VERSION 5.7 ;
  NOWIREEXTENSIONATPIN ON ;
  DIVIDERCHAR "/" ;
  BUSBITCHARS "[]" ;
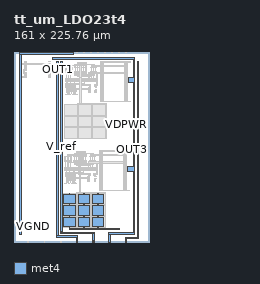
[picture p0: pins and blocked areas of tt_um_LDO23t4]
MACRO tt_um_LDO23t4
  CLASS BLOCK ;
  FOREIGN tt_um_LDO23t4 ;
  ORIGIN 0.000 0.000 ;
  SIZE 161.000 BY 225.760 ;
  PIN OUT3
    DIRECTION OUTPUT ;
    ANTENNAGATEAREA 46.000000 ;
    ANTENNADIFFAREA 186.759995 ;
    PORT
      LAYER met4 ;
        RECT 65.655 56.800 66.175 57.795 ;
        RECT 82.715 56.800 83.235 57.795 ;
        RECT 99.775 56.800 100.295 57.795 ;
        RECT 59.110 45.190 72.720 56.800 ;
        RECT 76.170 45.190 89.780 56.800 ;
        RECT 93.230 45.190 106.840 56.800 ;
        RECT 65.655 43.200 66.175 45.190 ;
        RECT 82.715 43.200 83.235 45.190 ;
        RECT 99.775 43.200 100.295 45.190 ;
        RECT 59.110 31.590 72.720 43.200 ;
        RECT 76.170 31.590 89.780 43.200 ;
        RECT 93.230 31.590 106.840 43.200 ;
        RECT 65.655 29.600 66.175 31.590 ;
        RECT 82.715 29.600 83.235 31.590 ;
        RECT 99.775 29.600 100.295 31.590 ;
        RECT 59.110 17.990 72.720 29.600 ;
        RECT 76.170 17.990 89.780 29.600 ;
        RECT 93.230 17.990 106.840 29.600 ;
        RECT 65.655 16.615 66.360 17.990 ;
        RECT 82.630 16.615 83.335 17.990 ;
        RECT 99.530 16.615 100.565 17.990 ;
        RECT 65.595 14.805 125.650 16.615 ;
        RECT 146.495 5.725 148.495 214.950 ;
        RECT 132.100 3.725 148.495 5.725 ;
        RECT 132.105 2.385 134.105 3.725 ;
        RECT 132.100 1.800 134.105 2.385 ;
        RECT 132.105 1.620 134.105 1.800 ;
        RECT 132.110 1.000 134.105 1.620 ;
        RECT 132.110 0.005 134.110 1.000 ;
        RECT 132.490 0.000 133.390 0.005 ;
    END
  END OUT2
  PIN V_ref
    DIRECTION INPUT ;
    USE POWER ;
    PORT
      LAYER met4 ;
        RECT 55.775 12.630 57.775 214.950 ;
        RECT 55.775 11.815 57.780 12.630 ;
        RECT 55.775 11.810 91.580 11.815 ;
        RECT 55.775 9.815 95.175 11.810 ;
        RECT 93.175 1.570 95.175 9.815 ;
        RECT 93.180 1.000 95.175 1.570 ;
        RECT 93.180 0.000 95.180 1.000 ;
    END
  END V_ref
  PIN VGND
    DIRECTION INOUT ;
    USE GROUND ;
    PORT
      LAYER met4 ;
        RECT 30.670 224.760 30.970 225.760 ;
        RECT 33.430 224.760 33.730 225.760 ;
        RECT 36.190 224.760 36.490 225.760 ;
        RECT 38.950 224.760 39.250 225.760 ;
        RECT 41.710 224.760 42.010 225.760 ;
        RECT 44.470 224.760 44.770 225.760 ;
        RECT 47.230 224.760 47.530 225.760 ;
        RECT 49.990 224.760 50.290 225.760 ;
        RECT 52.750 224.760 53.050 225.760 ;
        RECT 55.510 224.760 55.810 225.760 ;
        RECT 58.270 224.760 58.570 225.760 ;
        RECT 61.030 224.760 61.330 225.760 ;
        RECT 63.790 224.760 64.090 225.760 ;
        RECT 66.550 224.760 66.850 225.760 ;
        RECT 68.720 224.760 70.355 225.760 ;
        RECT 6.770 222.835 70.355 224.760 ;
        RECT 6.770 8.490 8.770 222.835 ;
    END
  END VGND
  PIN VDPWR
    DIRECTION INOUT ;
    USE POWER ;
    PORT
      LAYER met4 ;
        RECT 46.205 217.160 143.725 219.085 ;
        RECT 141.725 194.975 143.725 217.160 ;
        RECT 135.650 189.520 143.725 194.975 ;
        RECT 141.725 89.175 143.725 189.520 ;
        RECT 134.815 83.720 143.725 89.175 ;
        RECT 141.725 10.910 143.725 83.720 ;
        RECT 112.690 8.910 143.725 10.910 ;
        RECT 112.690 0.000 114.690 8.910 ;
    END
  END VDPWR
  PIN OUT1
    DIRECTION OUTPUT ;
    USE SIGNAL ;
    PORT
      LAYER met4 ;
        RECT 50.995 7.790 53.005 214.950 ;
        RECT 70.380 7.795 75.985 7.800 ;
        RECT 54.605 7.790 75.985 7.795 ;
        RECT 50.995 5.790 75.985 7.790 ;
        RECT 73.965 0.000 75.985 5.790 ;
    END
  END OUT1
  OBS
      LAYER pwell ;
        RECT 60.880 193.420 69.170 194.180 ;
        RECT 69.750 193.420 85.780 194.180 ;
        RECT 86.350 193.420 97.220 194.180 ;
        RECT 60.880 191.830 69.170 192.590 ;
        RECT 69.750 191.830 85.780 192.590 ;
        RECT 86.350 191.830 97.220 192.590 ;
        RECT 60.880 190.240 69.170 191.000 ;
        RECT 69.750 190.240 85.780 191.000 ;
        RECT 86.350 190.240 97.220 191.000 ;
        RECT 60.040 87.625 68.330 88.385 ;
        RECT 68.910 87.625 84.940 88.385 ;
        RECT 85.510 87.625 96.380 88.385 ;
        RECT 60.040 86.035 68.330 86.795 ;
        RECT 68.910 86.035 84.940 86.795 ;
        RECT 85.510 86.035 96.380 86.795 ;
        RECT 60.040 84.445 68.330 85.205 ;
        RECT 68.910 84.445 84.940 85.205 ;
        RECT 85.510 84.445 96.380 85.205 ;
      LAYER li1 ;
        RECT 12.540 214.520 14.700 214.870 ;
        RECT 40.790 214.520 42.950 214.870 ;
        RECT 12.540 213.690 14.700 214.040 ;
        RECT 102.550 213.740 103.550 213.910 ;
        RECT 103.840 213.740 104.840 213.910 ;
        RECT 105.130 213.740 106.130 213.910 ;
        RECT 106.420 213.740 107.420 213.910 ;
        RECT 107.710 213.740 108.710 213.910 ;
        RECT 109.000 213.740 110.000 213.910 ;
        RECT 110.290 213.740 111.290 213.910 ;
        RECT 111.580 213.740 112.580 213.910 ;
        RECT 112.870 213.740 113.870 213.910 ;
        RECT 114.160 213.740 115.160 213.910 ;
        RECT 115.450 213.740 116.450 213.910 ;
        RECT 116.740 213.740 117.740 213.910 ;
        RECT 121.750 213.740 122.750 213.910 ;
        RECT 123.040 213.740 124.040 213.910 ;
        RECT 124.330 213.740 125.330 213.910 ;
        RECT 125.620 213.740 126.620 213.910 ;
        RECT 126.910 213.740 127.910 213.910 ;
        RECT 128.200 213.740 129.200 213.910 ;
        RECT 129.490 213.740 130.490 213.910 ;
        RECT 130.780 213.740 131.780 213.910 ;
        RECT 132.070 213.740 133.070 213.910 ;
        RECT 133.360 213.740 134.360 213.910 ;
        RECT 134.650 213.740 135.650 213.910 ;
        RECT 135.940 213.740 136.940 213.910 ;
        RECT 137.230 213.740 138.230 213.910 ;
        RECT 12.540 212.860 14.700 213.210 ;
        RECT 12.540 212.030 14.700 212.380 ;
        RECT 40.790 212.030 42.950 212.380 ;
        RECT 12.540 209.830 14.700 210.180 ;
        RECT 40.790 209.830 42.950 210.180 ;
        RECT 12.540 209.000 14.700 209.350 ;
        RECT 12.540 208.170 14.700 208.520 ;
        RECT 40.790 208.170 42.950 208.520 ;
        RECT 12.540 207.340 14.700 207.690 ;
        RECT 40.790 207.340 42.950 207.690 ;
        RECT 61.300 207.560 62.300 207.730 ;
        RECT 62.695 207.560 63.485 207.730 ;
        RECT 63.985 207.560 64.775 207.730 ;
        RECT 65.275 207.560 66.065 207.730 ;
        RECT 66.565 207.560 67.355 207.730 ;
        RECT 67.750 207.560 68.750 207.730 ;
        RECT 71.575 207.560 72.365 207.730 ;
        RECT 72.865 207.560 73.655 207.730 ;
        RECT 74.155 207.560 74.945 207.730 ;
        RECT 75.445 207.560 76.235 207.730 ;
        RECT 76.735 207.560 77.525 207.730 ;
        RECT 78.025 207.560 78.815 207.730 ;
        RECT 79.315 207.560 80.105 207.730 ;
        RECT 80.605 207.560 81.395 207.730 ;
        RECT 81.895 207.560 82.685 207.730 ;
        RECT 83.185 207.560 83.975 207.730 ;
        RECT 84.475 207.560 85.265 207.730 ;
        RECT 85.765 207.560 86.555 207.730 ;
        RECT 90.755 207.560 91.545 207.730 ;
        RECT 92.045 207.560 92.835 207.730 ;
        RECT 93.335 207.560 94.125 207.730 ;
        RECT 94.625 207.560 95.415 207.730 ;
        RECT 95.915 207.560 96.705 207.730 ;
        RECT 97.205 207.560 97.995 207.730 ;
        RECT 12.540 206.510 14.700 206.860 ;
        RECT 40.790 206.510 42.950 206.860 ;
        RECT 12.540 205.680 14.700 206.030 ;
        RECT 40.790 205.680 42.950 206.030 ;
        RECT 12.540 204.850 14.700 205.200 ;
        RECT 40.790 204.850 42.950 205.200 ;
        RECT 12.540 204.020 14.700 204.370 ;
        RECT 40.790 204.020 42.950 204.370 ;
        RECT 12.540 203.190 14.700 203.540 ;
        RECT 40.790 203.190 42.950 203.540 ;
        RECT 61.070 202.305 61.240 207.345 ;
        RECT 62.360 202.305 62.530 207.345 ;
        RECT 64.940 202.305 65.110 207.345 ;
        RECT 67.520 202.305 67.690 207.345 ;
        RECT 68.810 202.305 68.980 207.345 ;
        RECT 72.530 202.305 72.700 207.345 ;
        RECT 75.110 202.305 75.280 207.345 ;
        RECT 77.690 202.305 77.860 207.345 ;
        RECT 80.270 202.305 80.440 207.345 ;
        RECT 82.850 202.305 83.020 207.345 ;
        RECT 85.430 202.305 85.600 207.345 ;
        RECT 91.710 202.305 91.880 207.345 ;
        RECT 94.290 202.305 94.460 207.345 ;
        RECT 96.870 202.305 97.040 207.345 ;
        RECT 61.300 201.920 62.300 202.090 ;
        RECT 62.695 201.920 63.485 202.090 ;
        RECT 63.985 201.920 64.775 202.090 ;
        RECT 65.275 201.920 66.065 202.090 ;
        RECT 66.565 201.920 67.355 202.090 ;
        RECT 67.750 201.920 68.750 202.090 ;
        RECT 71.575 201.920 72.365 202.090 ;
        RECT 72.865 201.920 73.655 202.090 ;
        RECT 74.155 201.920 74.945 202.090 ;
        RECT 75.445 201.920 76.235 202.090 ;
        RECT 76.735 201.920 77.525 202.090 ;
        RECT 78.025 201.920 78.815 202.090 ;
        RECT 79.315 201.920 80.105 202.090 ;
        RECT 80.605 201.920 81.395 202.090 ;
        RECT 81.895 201.920 82.685 202.090 ;
        RECT 83.185 201.920 83.975 202.090 ;
        RECT 84.475 201.920 85.265 202.090 ;
        RECT 85.765 201.920 86.555 202.090 ;
        RECT 90.755 201.920 91.545 202.090 ;
        RECT 92.045 201.920 92.835 202.090 ;
        RECT 93.335 201.920 94.125 202.090 ;
        RECT 94.625 201.920 95.415 202.090 ;
        RECT 95.915 201.920 96.705 202.090 ;
        RECT 97.205 201.920 97.995 202.090 ;
        RECT 12.540 200.990 14.700 201.340 ;
        RECT 40.790 200.990 42.950 201.340 ;
        RECT 12.540 200.160 14.700 200.510 ;
        RECT 40.790 200.160 42.950 200.510 ;
        RECT 12.540 199.330 14.700 199.680 ;
        RECT 40.790 199.330 42.950 199.680 ;
        RECT 12.540 198.500 14.700 198.850 ;
        RECT 40.790 198.500 42.950 198.850 ;
        RECT 12.540 197.670 14.700 198.020 ;
        RECT 40.790 197.670 42.950 198.020 ;
        RECT 12.540 196.840 14.700 197.190 ;
        RECT 40.790 196.840 42.950 197.190 ;
        RECT 12.540 196.010 14.700 196.360 ;
        RECT 40.790 196.010 42.950 196.360 ;
        RECT 12.540 195.180 14.700 195.530 ;
        RECT 40.790 195.180 42.950 195.530 ;
        RECT 61.405 192.650 62.195 192.820 ;
        RECT 62.695 192.650 63.485 192.820 ;
        RECT 66.565 192.650 67.355 192.820 ;
        RECT 67.855 192.650 68.645 192.820 ;
        RECT 71.565 192.650 72.355 192.820 ;
        RECT 72.855 192.650 73.645 192.820 ;
        RECT 74.145 192.650 74.935 192.820 ;
        RECT 75.435 192.650 76.225 192.820 ;
        RECT 76.725 192.650 77.515 192.820 ;
        RECT 78.015 192.650 78.805 192.820 ;
        RECT 79.305 192.650 80.095 192.820 ;
        RECT 80.595 192.650 81.385 192.820 ;
        RECT 81.885 192.650 82.675 192.820 ;
        RECT 83.175 192.650 83.965 192.820 ;
        RECT 88.165 192.650 88.955 192.820 ;
        RECT 89.455 192.650 90.245 192.820 ;
        RECT 90.745 192.650 91.535 192.820 ;
        RECT 92.035 192.650 92.825 192.820 ;
        RECT 93.325 192.650 94.115 192.820 ;
        RECT 94.615 192.650 95.405 192.820 ;
        RECT 61.070 191.940 61.240 192.480 ;
        RECT 62.360 191.940 62.530 192.480 ;
        RECT 63.650 191.940 63.820 192.480 ;
        RECT 64.940 191.940 65.110 192.480 ;
        RECT 66.230 191.940 66.400 192.480 ;
        RECT 67.520 191.940 67.690 192.480 ;
        RECT 68.810 191.940 68.980 192.480 ;
        RECT 72.520 191.940 72.690 192.480 ;
        RECT 75.100 191.940 75.270 192.480 ;
        RECT 77.680 191.940 77.850 192.480 ;
        RECT 80.260 191.940 80.430 192.480 ;
        RECT 82.840 191.940 83.010 192.480 ;
        RECT 89.120 191.940 89.290 192.480 ;
        RECT 91.700 191.940 91.870 192.480 ;
        RECT 94.280 191.940 94.450 192.480 ;
        RECT 61.405 191.600 62.195 191.770 ;
        RECT 62.695 191.600 63.485 191.770 ;
        RECT 66.565 191.600 67.355 191.770 ;
        RECT 67.855 191.600 68.645 191.770 ;
        RECT 71.565 191.600 72.355 191.770 ;
        RECT 72.855 191.600 73.645 191.770 ;
        RECT 74.145 191.600 74.935 191.770 ;
        RECT 75.435 191.600 76.225 191.770 ;
        RECT 76.725 191.600 77.515 191.770 ;
        RECT 78.015 191.600 78.805 191.770 ;
        RECT 79.305 191.600 80.095 191.770 ;
        RECT 80.595 191.600 81.385 191.770 ;
        RECT 81.885 191.600 82.675 191.770 ;
        RECT 83.175 191.600 83.965 191.770 ;
        RECT 88.165 191.600 88.955 191.770 ;
        RECT 89.455 191.600 90.245 191.770 ;
        RECT 90.745 191.600 91.535 191.770 ;
        RECT 92.035 191.600 92.825 191.770 ;
        RECT 93.325 191.600 94.115 191.770 ;
        RECT 94.615 191.600 95.405 191.770 ;
        RECT 67.525 188.505 68.985 188.675 ;
        RECT 67.525 188.160 67.695 188.505 ;
        RECT 62.115 187.990 67.695 188.160 ;
        RECT 61.805 187.235 61.975 187.775 ;
        RECT 63.095 187.235 63.265 187.775 ;
        RECT 64.385 187.020 64.555 187.990 ;
        RECT 65.675 187.020 65.845 187.990 ;
        RECT 66.965 187.055 67.135 187.990 ;
        RECT 67.525 187.235 67.695 187.990 ;
        RECT 68.815 187.235 68.985 188.505 ;
        RECT 67.525 187.065 68.985 187.235 ;
        RECT 67.525 187.055 67.695 187.065 ;
        RECT 66.625 187.020 67.695 187.055 ;
        RECT 62.115 186.885 67.695 187.020 ;
        RECT 89.140 186.980 91.300 187.330 ;
        RECT 95.520 186.980 97.680 187.330 ;
        RECT 62.115 186.850 66.795 186.885 ;
        RECT 67.865 186.525 68.645 186.695 ;
        RECT 71.225 186.575 72.685 186.610 ;
        RECT 62.115 186.310 62.955 186.480 ;
        RECT 63.435 186.310 64.215 186.480 ;
        RECT 64.725 186.310 65.505 186.480 ;
        RECT 65.675 186.310 67.135 186.480 ;
        RECT 69.715 186.440 72.685 186.575 ;
        RECT 72.855 186.440 73.635 186.610 ;
        RECT 69.715 186.405 71.395 186.440 ;
        RECT 61.805 185.555 61.975 186.095 ;
        RECT 63.095 185.555 63.265 186.095 ;
        RECT 65.675 185.340 65.845 186.310 ;
        RECT 66.965 185.340 67.135 186.310 ;
        RECT 67.525 185.470 67.695 186.310 ;
        RECT 70.665 185.650 70.835 186.190 ;
        RECT 71.225 185.435 71.395 186.405 ;
        RECT 62.115 185.170 62.955 185.340 ;
        RECT 63.435 185.170 64.215 185.340 ;
        RECT 64.725 185.170 65.505 185.340 ;
        RECT 65.675 185.170 67.135 185.340 ;
        RECT 69.715 185.380 71.395 185.435 ;
        RECT 72.515 185.380 72.685 186.440 ;
        RECT 89.140 186.150 91.300 186.500 ;
        RECT 95.520 186.150 97.680 186.500 ;
        RECT 69.715 185.265 72.685 185.380 ;
        RECT 67.865 185.085 68.645 185.255 ;
        RECT 71.225 185.210 72.685 185.265 ;
        RECT 72.855 185.210 73.635 185.380 ;
        RECT 89.140 185.320 91.300 185.670 ;
        RECT 95.520 185.320 97.680 185.670 ;
        RECT 62.115 184.715 67.135 184.800 ;
        RECT 62.115 184.630 68.985 184.715 ;
        RECT 61.805 183.875 61.975 184.415 ;
        RECT 63.095 183.875 63.265 184.415 ;
        RECT 64.385 183.660 64.555 184.630 ;
        RECT 65.675 183.660 65.845 184.630 ;
        RECT 66.965 184.545 68.985 184.630 ;
        RECT 66.965 183.660 67.135 184.545 ;
        RECT 67.525 183.660 67.695 184.545 ;
        RECT 62.115 183.490 67.695 183.660 ;
        RECT 67.525 183.275 67.695 183.490 ;
        RECT 68.815 183.275 68.985 184.545 ;
        RECT 67.525 183.105 68.985 183.275 ;
        RECT 88.270 183.040 90.430 183.390 ;
        RECT 96.400 183.040 98.560 183.390 ;
        RECT 88.270 182.210 90.430 182.560 ;
        RECT 88.270 181.380 90.430 181.730 ;
        RECT 96.400 181.380 98.560 181.730 ;
        RECT 62.885 179.840 63.665 180.010 ;
        RECT 64.145 179.840 64.985 180.010 ;
        RECT 66.025 179.760 66.805 179.930 ;
        RECT 67.315 179.760 68.435 179.930 ;
        RECT 68.605 179.760 69.385 179.930 ;
        RECT 69.895 179.760 70.675 179.930 ;
        RECT 71.405 179.760 72.865 179.930 ;
        RECT 73.035 179.760 73.815 179.930 ;
        RECT 63.835 178.960 64.005 179.670 ;
        RECT 65.125 178.960 65.295 179.670 ;
        RECT 65.685 179.050 65.855 179.590 ;
        RECT 68.265 178.880 68.435 179.760 ;
        RECT 70.845 179.050 71.015 179.590 ;
        RECT 71.405 178.880 71.575 179.760 ;
        RECT 72.695 178.880 72.865 179.760 ;
        RECT 88.730 179.160 90.890 179.510 ;
        RECT 95.980 179.160 98.140 179.510 ;
        RECT 62.885 178.620 63.665 178.790 ;
        RECT 64.145 178.620 64.985 178.790 ;
        RECT 66.025 178.710 66.805 178.880 ;
        RECT 67.315 178.710 68.435 178.880 ;
        RECT 68.605 178.710 69.385 178.880 ;
        RECT 69.895 178.710 70.675 178.880 ;
        RECT 71.405 178.710 72.865 178.880 ;
        RECT 73.035 178.710 73.815 178.880 ;
        RECT 88.730 178.330 90.890 178.680 ;
        RECT 88.730 177.500 90.890 177.850 ;
        RECT 95.980 177.500 98.140 177.850 ;
        RECT 61.330 175.050 63.490 175.400 ;
        RECT 65.080 175.050 67.240 175.400 ;
        RECT 69.455 175.050 71.615 175.400 ;
        RECT 73.205 175.050 75.365 175.400 ;
        RECT 102.550 167.100 103.550 167.270 ;
        RECT 103.840 167.100 104.840 167.270 ;
        RECT 105.130 167.100 106.130 167.270 ;
        RECT 106.420 167.100 107.420 167.270 ;
        RECT 107.710 167.100 108.710 167.270 ;
        RECT 109.000 167.100 110.000 167.270 ;
        RECT 110.290 167.100 111.290 167.270 ;
        RECT 111.580 167.100 112.580 167.270 ;
        RECT 112.870 167.100 113.870 167.270 ;
        RECT 114.160 167.100 115.160 167.270 ;
        RECT 115.450 167.100 116.450 167.270 ;
        RECT 116.740 167.100 117.740 167.270 ;
        RECT 121.750 167.100 122.750 167.270 ;
        RECT 123.040 167.100 124.040 167.270 ;
        RECT 124.330 167.100 125.330 167.270 ;
        RECT 125.620 167.100 126.620 167.270 ;
        RECT 126.910 167.100 127.910 167.270 ;
        RECT 128.200 167.100 129.200 167.270 ;
        RECT 129.490 167.100 130.490 167.270 ;
        RECT 130.780 167.100 131.780 167.270 ;
        RECT 132.070 167.100 133.070 167.270 ;
        RECT 133.360 167.100 134.360 167.270 ;
        RECT 134.650 167.100 135.650 167.270 ;
        RECT 135.940 167.100 136.940 167.270 ;
        RECT 137.230 167.100 138.230 167.270 ;
        RECT 101.710 107.945 102.710 108.115 ;
        RECT 103.000 107.945 104.000 108.115 ;
        RECT 104.290 107.945 105.290 108.115 ;
        RECT 105.580 107.945 106.580 108.115 ;
        RECT 106.870 107.945 107.870 108.115 ;
        RECT 108.160 107.945 109.160 108.115 ;
        RECT 109.450 107.945 110.450 108.115 ;
        RECT 110.740 107.945 111.740 108.115 ;
        RECT 112.030 107.945 113.030 108.115 ;
        RECT 113.320 107.945 114.320 108.115 ;
        RECT 114.610 107.945 115.610 108.115 ;
        RECT 115.900 107.945 116.900 108.115 ;
        RECT 120.910 107.945 121.910 108.115 ;
        RECT 122.200 107.945 123.200 108.115 ;
        RECT 123.490 107.945 124.490 108.115 ;
        RECT 124.780 107.945 125.780 108.115 ;
        RECT 126.070 107.945 127.070 108.115 ;
        RECT 127.360 107.945 128.360 108.115 ;
        RECT 128.650 107.945 129.650 108.115 ;
        RECT 129.940 107.945 130.940 108.115 ;
        RECT 131.230 107.945 132.230 108.115 ;
        RECT 132.520 107.945 133.520 108.115 ;
        RECT 133.810 107.945 134.810 108.115 ;
        RECT 135.100 107.945 136.100 108.115 ;
        RECT 136.390 107.945 137.390 108.115 ;
        RECT 60.460 101.765 61.460 101.935 ;
        RECT 61.855 101.765 62.645 101.935 ;
        RECT 63.145 101.765 63.935 101.935 ;
        RECT 64.435 101.765 65.225 101.935 ;
        RECT 65.725 101.765 66.515 101.935 ;
        RECT 66.910 101.765 67.910 101.935 ;
        RECT 70.735 101.765 71.525 101.935 ;
        RECT 72.025 101.765 72.815 101.935 ;
        RECT 73.315 101.765 74.105 101.935 ;
        RECT 74.605 101.765 75.395 101.935 ;
        RECT 75.895 101.765 76.685 101.935 ;
        RECT 77.185 101.765 77.975 101.935 ;
        RECT 78.475 101.765 79.265 101.935 ;
        RECT 79.765 101.765 80.555 101.935 ;
        RECT 81.055 101.765 81.845 101.935 ;
        RECT 82.345 101.765 83.135 101.935 ;
        RECT 83.635 101.765 84.425 101.935 ;
        RECT 84.925 101.765 85.715 101.935 ;
        RECT 89.915 101.765 90.705 101.935 ;
        RECT 91.205 101.765 91.995 101.935 ;
        RECT 92.495 101.765 93.285 101.935 ;
        RECT 93.785 101.765 94.575 101.935 ;
        RECT 95.075 101.765 95.865 101.935 ;
        RECT 96.365 101.765 97.155 101.935 ;
        RECT 60.230 96.510 60.400 101.550 ;
        RECT 61.520 96.510 61.690 101.550 ;
        RECT 64.100 96.510 64.270 101.550 ;
        RECT 66.680 96.510 66.850 101.550 ;
        RECT 67.970 96.510 68.140 101.550 ;
        RECT 71.690 96.510 71.860 101.550 ;
        RECT 74.270 96.510 74.440 101.550 ;
        RECT 76.850 96.510 77.020 101.550 ;
        RECT 79.430 96.510 79.600 101.550 ;
        RECT 82.010 96.510 82.180 101.550 ;
        RECT 84.590 96.510 84.760 101.550 ;
        RECT 90.870 96.510 91.040 101.550 ;
        RECT 93.450 96.510 93.620 101.550 ;
        RECT 96.030 96.510 96.200 101.550 ;
        RECT 60.460 96.125 61.460 96.295 ;
        RECT 61.855 96.125 62.645 96.295 ;
        RECT 63.145 96.125 63.935 96.295 ;
        RECT 64.435 96.125 65.225 96.295 ;
        RECT 65.725 96.125 66.515 96.295 ;
        RECT 66.910 96.125 67.910 96.295 ;
        RECT 70.735 96.125 71.525 96.295 ;
        RECT 72.025 96.125 72.815 96.295 ;
        RECT 73.315 96.125 74.105 96.295 ;
        RECT 74.605 96.125 75.395 96.295 ;
        RECT 75.895 96.125 76.685 96.295 ;
        RECT 77.185 96.125 77.975 96.295 ;
        RECT 78.475 96.125 79.265 96.295 ;
        RECT 79.765 96.125 80.555 96.295 ;
        RECT 81.055 96.125 81.845 96.295 ;
        RECT 82.345 96.125 83.135 96.295 ;
        RECT 83.635 96.125 84.425 96.295 ;
        RECT 84.925 96.125 85.715 96.295 ;
        RECT 89.915 96.125 90.705 96.295 ;
        RECT 91.205 96.125 91.995 96.295 ;
        RECT 92.495 96.125 93.285 96.295 ;
        RECT 93.785 96.125 94.575 96.295 ;
        RECT 95.075 96.125 95.865 96.295 ;
        RECT 96.365 96.125 97.155 96.295 ;
        RECT 60.565 86.855 61.355 87.025 ;
        RECT 61.855 86.855 62.645 87.025 ;
        RECT 65.725 86.855 66.515 87.025 ;
        RECT 67.015 86.855 67.805 87.025 ;
        RECT 70.725 86.855 71.515 87.025 ;
        RECT 72.015 86.855 72.805 87.025 ;
        RECT 73.305 86.855 74.095 87.025 ;
        RECT 74.595 86.855 75.385 87.025 ;
        RECT 75.885 86.855 76.675 87.025 ;
        RECT 77.175 86.855 77.965 87.025 ;
        RECT 78.465 86.855 79.255 87.025 ;
        RECT 79.755 86.855 80.545 87.025 ;
        RECT 81.045 86.855 81.835 87.025 ;
        RECT 82.335 86.855 83.125 87.025 ;
        RECT 87.325 86.855 88.115 87.025 ;
        RECT 88.615 86.855 89.405 87.025 ;
        RECT 89.905 86.855 90.695 87.025 ;
        RECT 91.195 86.855 91.985 87.025 ;
        RECT 92.485 86.855 93.275 87.025 ;
        RECT 93.775 86.855 94.565 87.025 ;
        RECT 60.230 86.145 60.400 86.685 ;
        RECT 61.520 86.145 61.690 86.685 ;
        RECT 62.810 86.145 62.980 86.685 ;
        RECT 64.100 86.145 64.270 86.685 ;
        RECT 65.390 86.145 65.560 86.685 ;
        RECT 66.680 86.145 66.850 86.685 ;
        RECT 67.970 86.145 68.140 86.685 ;
        RECT 71.680 86.145 71.850 86.685 ;
        RECT 74.260 86.145 74.430 86.685 ;
        RECT 76.840 86.145 77.010 86.685 ;
        RECT 79.420 86.145 79.590 86.685 ;
        RECT 82.000 86.145 82.170 86.685 ;
        RECT 88.280 86.145 88.450 86.685 ;
        RECT 90.860 86.145 91.030 86.685 ;
        RECT 93.440 86.145 93.610 86.685 ;
        RECT 60.565 85.805 61.355 85.975 ;
        RECT 61.855 85.805 62.645 85.975 ;
        RECT 65.725 85.805 66.515 85.975 ;
        RECT 67.015 85.805 67.805 85.975 ;
        RECT 70.725 85.805 71.515 85.975 ;
        RECT 72.015 85.805 72.805 85.975 ;
        RECT 73.305 85.805 74.095 85.975 ;
        RECT 74.595 85.805 75.385 85.975 ;
        RECT 75.885 85.805 76.675 85.975 ;
        RECT 77.175 85.805 77.965 85.975 ;
        RECT 78.465 85.805 79.255 85.975 ;
        RECT 79.755 85.805 80.545 85.975 ;
        RECT 81.045 85.805 81.835 85.975 ;
        RECT 82.335 85.805 83.125 85.975 ;
        RECT 87.325 85.805 88.115 85.975 ;
        RECT 88.615 85.805 89.405 85.975 ;
        RECT 89.905 85.805 90.695 85.975 ;
        RECT 91.195 85.805 91.985 85.975 ;
        RECT 92.485 85.805 93.275 85.975 ;
        RECT 93.775 85.805 94.565 85.975 ;
        RECT 66.685 82.710 68.145 82.880 ;
        RECT 66.685 82.365 66.855 82.710 ;
        RECT 61.275 82.195 66.855 82.365 ;
        RECT 60.965 81.440 61.135 81.980 ;
        RECT 62.255 81.440 62.425 81.980 ;
        RECT 63.545 81.225 63.715 82.195 ;
        RECT 64.835 81.225 65.005 82.195 ;
        RECT 66.125 81.260 66.295 82.195 ;
        RECT 66.685 81.440 66.855 82.195 ;
        RECT 67.975 81.440 68.145 82.710 ;
        RECT 66.685 81.270 68.145 81.440 ;
        RECT 66.685 81.260 66.855 81.270 ;
        RECT 65.785 81.225 66.855 81.260 ;
        RECT 61.275 81.090 66.855 81.225 ;
        RECT 88.300 81.185 90.460 81.535 ;
        RECT 94.680 81.185 96.840 81.535 ;
        RECT 61.275 81.055 65.955 81.090 ;
        RECT 67.025 80.730 67.805 80.900 ;
        RECT 70.385 80.780 71.845 80.815 ;
        RECT 61.275 80.515 62.115 80.685 ;
        RECT 62.595 80.515 63.375 80.685 ;
        RECT 63.885 80.515 64.665 80.685 ;
        RECT 64.835 80.515 66.295 80.685 ;
        RECT 68.875 80.645 71.845 80.780 ;
        RECT 72.015 80.645 72.795 80.815 ;
        RECT 68.875 80.610 70.555 80.645 ;
        RECT 60.965 79.760 61.135 80.300 ;
        RECT 62.255 79.760 62.425 80.300 ;
        RECT 64.835 79.545 65.005 80.515 ;
        RECT 66.125 79.545 66.295 80.515 ;
        RECT 66.685 79.675 66.855 80.515 ;
        RECT 69.825 79.855 69.995 80.395 ;
        RECT 70.385 79.640 70.555 80.610 ;
        RECT 61.275 79.375 62.115 79.545 ;
        RECT 62.595 79.375 63.375 79.545 ;
        RECT 63.885 79.375 64.665 79.545 ;
        RECT 64.835 79.375 66.295 79.545 ;
        RECT 68.875 79.585 70.555 79.640 ;
        RECT 71.675 79.585 71.845 80.645 ;
        RECT 88.300 80.355 90.460 80.705 ;
        RECT 94.680 80.355 96.840 80.705 ;
        RECT 68.875 79.470 71.845 79.585 ;
        RECT 67.025 79.290 67.805 79.460 ;
        RECT 70.385 79.415 71.845 79.470 ;
        RECT 72.015 79.415 72.795 79.585 ;
        RECT 88.300 79.525 90.460 79.875 ;
        RECT 94.680 79.525 96.840 79.875 ;
        RECT 61.275 78.920 66.295 79.005 ;
        RECT 61.275 78.835 68.145 78.920 ;
        RECT 60.965 78.080 61.135 78.620 ;
        RECT 62.255 78.080 62.425 78.620 ;
        RECT 63.545 77.865 63.715 78.835 ;
        RECT 64.835 77.865 65.005 78.835 ;
        RECT 66.125 78.750 68.145 78.835 ;
        RECT 66.125 77.865 66.295 78.750 ;
        RECT 66.685 77.865 66.855 78.750 ;
        RECT 61.275 77.695 66.855 77.865 ;
        RECT 66.685 77.480 66.855 77.695 ;
        RECT 67.975 77.480 68.145 78.750 ;
        RECT 66.685 77.310 68.145 77.480 ;
        RECT 87.430 77.245 89.590 77.595 ;
        RECT 95.560 77.245 97.720 77.595 ;
        RECT 87.430 76.415 89.590 76.765 ;
        RECT 87.430 75.585 89.590 75.935 ;
        RECT 95.560 75.585 97.720 75.935 ;
        RECT 62.045 74.045 62.825 74.215 ;
        RECT 63.305 74.045 64.145 74.215 ;
        RECT 65.185 73.965 65.965 74.135 ;
        RECT 66.475 73.965 67.595 74.135 ;
        RECT 67.765 73.965 68.545 74.135 ;
        RECT 69.055 73.965 69.835 74.135 ;
        RECT 70.565 73.965 72.025 74.135 ;
        RECT 72.195 73.965 72.975 74.135 ;
        RECT 62.995 73.165 63.165 73.875 ;
        RECT 64.285 73.165 64.455 73.875 ;
        RECT 64.845 73.255 65.015 73.795 ;
        RECT 67.425 73.085 67.595 73.965 ;
        RECT 70.005 73.255 70.175 73.795 ;
        RECT 70.565 73.085 70.735 73.965 ;
        RECT 71.855 73.085 72.025 73.965 ;
        RECT 87.890 73.365 90.050 73.715 ;
        RECT 95.140 73.365 97.300 73.715 ;
        RECT 62.045 72.825 62.825 72.995 ;
        RECT 63.305 72.825 64.145 72.995 ;
        RECT 65.185 72.915 65.965 73.085 ;
        RECT 66.475 72.915 67.595 73.085 ;
        RECT 67.765 72.915 68.545 73.085 ;
        RECT 69.055 72.915 69.835 73.085 ;
        RECT 70.565 72.915 72.025 73.085 ;
        RECT 72.195 72.915 72.975 73.085 ;
        RECT 87.890 72.535 90.050 72.885 ;
        RECT 87.890 71.705 90.050 72.055 ;
        RECT 95.140 71.705 97.300 72.055 ;
        RECT 60.490 69.255 62.650 69.605 ;
        RECT 64.240 69.255 66.400 69.605 ;
        RECT 68.615 69.255 70.775 69.605 ;
        RECT 72.365 69.255 74.525 69.605 ;
        RECT 101.710 61.305 102.710 61.475 ;
        RECT 103.000 61.305 104.000 61.475 ;
        RECT 104.290 61.305 105.290 61.475 ;
        RECT 105.580 61.305 106.580 61.475 ;
        RECT 106.870 61.305 107.870 61.475 ;
        RECT 108.160 61.305 109.160 61.475 ;
        RECT 109.450 61.305 110.450 61.475 ;
        RECT 110.740 61.305 111.740 61.475 ;
        RECT 112.030 61.305 113.030 61.475 ;
        RECT 113.320 61.305 114.320 61.475 ;
        RECT 114.610 61.305 115.610 61.475 ;
        RECT 115.900 61.305 116.900 61.475 ;
        RECT 120.910 61.305 121.910 61.475 ;
        RECT 122.200 61.305 123.200 61.475 ;
        RECT 123.490 61.305 124.490 61.475 ;
        RECT 124.780 61.305 125.780 61.475 ;
        RECT 126.070 61.305 127.070 61.475 ;
        RECT 127.360 61.305 128.360 61.475 ;
        RECT 128.650 61.305 129.650 61.475 ;
        RECT 129.940 61.305 130.940 61.475 ;
        RECT 131.230 61.305 132.230 61.475 ;
        RECT 132.520 61.305 133.520 61.475 ;
        RECT 133.810 61.305 134.810 61.475 ;
        RECT 135.100 61.305 136.100 61.475 ;
        RECT 136.390 61.305 137.390 61.475 ;
      LAYER met1 ;
        RECT 12.570 214.570 14.675 214.820 ;
        RECT 40.815 214.570 42.920 214.820 ;
        RECT 12.570 212.910 14.675 213.990 ;
        RECT 102.730 213.940 103.370 214.020 ;
        RECT 104.020 213.940 104.660 214.020 ;
        RECT 105.310 213.940 105.950 214.020 ;
        RECT 106.600 213.940 107.240 214.020 ;
        RECT 107.890 213.940 108.530 214.020 ;
        RECT 109.180 213.940 109.820 214.020 ;
        RECT 110.470 213.940 111.110 214.020 ;
        RECT 111.760 213.940 112.400 214.020 ;
        RECT 113.050 213.940 113.690 214.020 ;
        RECT 114.340 213.940 114.980 214.020 ;
        RECT 115.630 213.940 116.270 214.020 ;
        RECT 116.920 213.940 117.560 214.020 ;
        RECT 121.930 213.940 122.570 214.020 ;
        RECT 123.220 213.940 123.860 214.020 ;
        RECT 124.510 213.940 125.150 214.020 ;
        RECT 125.800 213.940 126.440 214.020 ;
        RECT 127.090 213.940 127.730 214.020 ;
        RECT 128.380 213.940 129.020 214.020 ;
        RECT 129.670 213.940 130.310 214.020 ;
        RECT 130.960 213.940 131.600 214.020 ;
        RECT 132.250 213.940 132.890 214.020 ;
        RECT 133.540 213.940 134.180 214.020 ;
        RECT 134.830 213.940 135.470 214.020 ;
        RECT 136.120 213.940 136.760 214.020 ;
        RECT 137.410 213.940 138.050 214.020 ;
        RECT 102.675 213.710 103.425 213.940 ;
        RECT 103.965 213.710 104.715 213.940 ;
        RECT 105.255 213.710 106.005 213.940 ;
        RECT 106.545 213.710 107.295 213.940 ;
        RECT 107.835 213.710 108.585 213.940 ;
        RECT 109.125 213.710 109.875 213.940 ;
        RECT 110.415 213.710 111.165 213.940 ;
        RECT 111.705 213.710 112.455 213.940 ;
        RECT 112.995 213.710 113.745 213.940 ;
        RECT 114.285 213.710 115.035 213.940 ;
        RECT 115.575 213.710 116.325 213.940 ;
        RECT 116.865 213.710 117.615 213.940 ;
        RECT 121.875 213.710 122.625 213.940 ;
        RECT 123.165 213.710 123.915 213.940 ;
        RECT 124.455 213.710 125.205 213.940 ;
        RECT 125.745 213.710 126.495 213.940 ;
        RECT 127.035 213.710 127.785 213.940 ;
        RECT 128.325 213.710 129.075 213.940 ;
        RECT 129.615 213.710 130.365 213.940 ;
        RECT 130.905 213.710 131.655 213.940 ;
        RECT 132.195 213.710 132.945 213.940 ;
        RECT 133.485 213.710 134.235 213.940 ;
        RECT 134.775 213.710 135.525 213.940 ;
        RECT 136.065 213.710 136.815 213.940 ;
        RECT 137.355 213.710 138.105 213.940 ;
        RECT 102.730 213.700 103.370 213.710 ;
        RECT 104.020 213.700 104.660 213.710 ;
        RECT 105.310 213.700 105.950 213.710 ;
        RECT 106.600 213.700 107.240 213.710 ;
        RECT 107.890 213.700 108.530 213.710 ;
        RECT 109.180 213.700 109.820 213.710 ;
        RECT 110.470 213.700 111.110 213.710 ;
        RECT 111.760 213.700 112.400 213.710 ;
        RECT 113.050 213.700 113.690 213.710 ;
        RECT 114.340 213.700 114.980 213.710 ;
        RECT 115.630 213.700 116.270 213.710 ;
        RECT 116.920 213.700 117.560 213.710 ;
        RECT 121.930 213.700 122.570 213.710 ;
        RECT 123.220 213.700 123.860 213.710 ;
        RECT 124.510 213.700 125.150 213.710 ;
        RECT 125.800 213.700 126.440 213.710 ;
        RECT 127.090 213.700 127.730 213.710 ;
        RECT 128.380 213.700 129.020 213.710 ;
        RECT 129.670 213.700 130.310 213.710 ;
        RECT 130.960 213.700 131.600 213.710 ;
        RECT 132.250 213.700 132.890 213.710 ;
        RECT 133.540 213.700 134.180 213.710 ;
        RECT 134.830 213.700 135.470 213.710 ;
        RECT 136.120 213.700 136.760 213.710 ;
        RECT 137.410 213.700 138.050 213.710 ;
        RECT 75.035 212.610 75.355 213.250 ;
        RECT 80.195 212.610 80.515 213.250 ;
        RECT 85.355 212.610 85.675 213.250 ;
        RECT 12.570 212.080 14.675 212.330 ;
        RECT 40.815 212.080 42.920 212.330 ;
        RECT 72.455 210.855 72.775 211.495 ;
        RECT 12.570 209.880 14.675 210.130 ;
        RECT 40.815 209.880 42.920 210.130 ;
        RECT 12.570 208.220 14.675 209.300 ;
        RECT 64.865 209.145 65.185 209.785 ;
        RECT 71.655 209.780 71.975 209.785 ;
        RECT 71.655 209.145 72.295 209.780 ;
        RECT 12.570 206.560 14.675 207.640 ;
        RECT 40.815 207.390 42.920 208.470 ;
        RECT 61.040 207.855 62.745 207.860 ;
        RECT 61.040 207.535 63.470 207.855 ;
        RECT 64.010 207.760 64.760 207.855 ;
        RECT 64.005 207.535 64.760 207.760 ;
        RECT 12.570 204.900 14.675 205.980 ;
        RECT 40.815 205.730 42.920 206.810 ;
        RECT 11.320 203.735 14.675 204.650 ;
        RECT 40.815 204.070 42.920 205.150 ;
        RECT 11.320 200.805 12.255 203.735 ;
        RECT 12.570 203.240 14.675 203.490 ;
        RECT 40.815 203.240 42.920 203.490 ;
        RECT 61.040 202.125 61.270 207.535 ;
        RECT 61.425 207.530 62.175 207.535 ;
        RECT 62.715 207.530 63.465 207.535 ;
        RECT 64.005 207.530 64.755 207.535 ;
        RECT 62.330 203.015 62.560 207.325 ;
        RECT 62.330 202.325 62.565 203.015 ;
        RECT 62.335 202.125 62.565 202.325 ;
        RECT 61.040 201.805 63.470 202.125 ;
        RECT 64.010 202.120 64.760 202.125 ;
        RECT 64.005 201.890 64.760 202.120 ;
        RECT 64.010 201.805 64.760 201.890 ;
        RECT 61.040 201.800 62.565 201.805 ;
        RECT 64.060 201.800 64.700 201.805 ;
        RECT 12.570 201.040 14.675 201.290 ;
        RECT 40.815 201.040 42.920 201.290 ;
        RECT 11.320 199.890 14.675 200.805 ;
        RECT 12.570 198.550 14.675 199.630 ;
        RECT 40.815 199.380 42.920 200.460 ;
        RECT 12.570 196.890 14.675 197.970 ;
        RECT 40.815 197.720 42.920 198.800 ;
        RECT 12.570 196.310 12.890 196.665 ;
        RECT 12.570 196.060 14.675 196.310 ;
        RECT 40.815 196.060 42.920 197.140 ;
        RECT 12.570 195.705 12.890 196.060 ;
        RECT 12.570 195.230 14.675 195.480 ;
        RECT 40.815 195.230 42.920 195.480 ;
        RECT 62.335 192.850 62.565 201.800 ;
        RECT 64.910 200.520 65.140 209.145 ;
        RECT 71.975 209.140 72.295 209.145 ;
        RECT 67.315 207.855 69.010 207.860 ;
        RECT 65.300 207.760 66.050 207.855 ;
        RECT 66.590 207.760 69.010 207.855 ;
        RECT 65.295 207.535 66.050 207.760 ;
        RECT 66.585 207.535 69.010 207.760 ;
        RECT 65.295 207.530 66.045 207.535 ;
        RECT 66.585 207.530 67.335 207.535 ;
        RECT 67.875 207.530 68.625 207.535 ;
        RECT 67.490 203.005 67.720 207.325 ;
        RECT 67.490 202.325 67.725 203.005 ;
        RECT 67.495 202.130 67.725 202.325 ;
        RECT 68.780 202.130 69.010 207.535 ;
        RECT 71.595 207.530 72.345 207.850 ;
        RECT 67.315 202.125 69.010 202.130 ;
        RECT 65.300 202.120 66.050 202.125 ;
        RECT 66.590 202.120 69.010 202.125 ;
        RECT 65.295 201.890 66.050 202.120 ;
        RECT 66.585 201.890 69.010 202.120 ;
        RECT 65.300 201.805 66.050 201.890 ;
        RECT 66.590 201.805 69.010 201.890 ;
        RECT 65.350 201.800 65.990 201.805 ;
        RECT 66.640 201.800 67.280 201.805 ;
        RECT 64.865 199.880 65.185 200.520 ;
        RECT 62.770 192.850 63.410 192.940 ;
        RECT 61.040 192.620 62.565 192.850 ;
        RECT 62.715 192.620 63.465 192.850 ;
        RECT 61.040 191.800 61.270 192.620 ;
        RECT 62.330 191.800 62.565 192.620 ;
        RECT 61.040 191.570 62.565 191.800 ;
        RECT 62.715 191.570 63.465 191.800 ;
        RECT 62.770 191.480 63.410 191.570 ;
        RECT 63.620 190.925 63.850 192.460 ;
        RECT 64.910 191.960 65.140 199.880 ;
        RECT 66.640 192.850 67.280 192.940 ;
        RECT 67.495 192.850 67.725 201.805 ;
        RECT 71.595 201.800 72.345 202.120 ;
        RECT 72.500 198.650 72.730 210.855 ;
        RECT 72.885 207.530 73.635 207.850 ;
        RECT 74.175 207.530 74.925 207.850 ;
        RECT 72.885 201.800 73.635 202.120 ;
        RECT 74.175 201.800 74.925 202.120 ;
        RECT 72.455 198.010 72.775 198.650 ;
        RECT 75.080 197.050 75.310 212.610 ;
        RECT 77.615 210.855 77.935 211.495 ;
        RECT 75.465 207.530 76.215 207.850 ;
        RECT 76.755 207.530 77.505 207.850 ;
        RECT 77.665 207.325 77.895 210.855 ;
        RECT 78.045 207.530 78.795 207.850 ;
        RECT 79.335 207.530 80.085 207.850 ;
        RECT 77.660 202.325 77.895 207.325 ;
        RECT 75.465 201.800 76.215 202.120 ;
        RECT 76.755 201.800 77.505 202.120 ;
        RECT 77.665 198.650 77.895 202.325 ;
        RECT 78.045 201.800 78.795 202.120 ;
        RECT 79.335 201.800 80.085 202.120 ;
        RECT 77.615 198.010 77.935 198.650 ;
        RECT 75.035 196.410 75.355 197.050 ;
        RECT 66.585 192.620 67.335 192.850 ;
        RECT 67.495 192.620 69.010 192.850 ;
        RECT 71.585 192.620 72.335 192.940 ;
        RECT 72.875 192.620 73.625 192.940 ;
        RECT 74.165 192.620 74.915 192.940 ;
        RECT 75.455 192.620 76.205 192.940 ;
        RECT 76.745 192.620 77.495 192.940 ;
        RECT 67.495 192.460 67.725 192.620 ;
        RECT 66.200 190.935 66.430 192.460 ;
        RECT 67.490 192.445 67.725 192.460 ;
        RECT 67.490 191.800 67.720 192.445 ;
        RECT 68.780 191.800 69.010 192.620 ;
        RECT 77.665 192.460 77.895 198.010 ;
        RECT 80.240 197.050 80.470 212.610 ;
        RECT 82.775 210.855 83.095 211.495 ;
        RECT 80.625 207.530 81.375 207.850 ;
        RECT 81.915 207.530 82.665 207.850 ;
        RECT 80.625 201.800 81.375 202.120 ;
        RECT 81.915 201.800 82.665 202.120 ;
        RECT 82.820 198.650 83.050 210.855 ;
        RECT 83.205 207.530 83.955 207.850 ;
        RECT 84.495 207.530 85.245 207.850 ;
        RECT 83.205 201.800 83.955 202.120 ;
        RECT 84.495 201.800 85.245 202.120 ;
        RECT 82.775 198.010 83.095 198.650 ;
        RECT 85.400 197.050 85.630 212.610 ;
        RECT 91.635 208.535 91.955 209.870 ;
        RECT 85.785 207.530 86.535 207.850 ;
        RECT 90.830 207.760 91.470 207.850 ;
        RECT 90.775 207.530 91.525 207.760 ;
        RECT 85.785 201.800 86.535 202.120 ;
        RECT 90.775 201.890 91.525 202.120 ;
        RECT 90.830 201.800 91.470 201.890 ;
        RECT 91.680 200.910 91.910 208.535 ;
        RECT 92.120 207.760 92.760 207.850 ;
        RECT 93.410 207.760 94.050 211.495 ;
        RECT 94.260 209.815 94.490 210.095 ;
        RECT 94.215 208.535 94.535 209.815 ;
        RECT 92.065 207.530 92.815 207.760 ;
        RECT 93.355 207.530 94.105 207.760 ;
        RECT 92.065 201.890 92.815 202.120 ;
        RECT 93.355 201.890 94.105 202.120 ;
        RECT 92.120 201.800 92.760 201.890 ;
        RECT 89.055 199.630 89.375 200.910 ;
        RECT 91.635 199.630 91.955 200.910 ;
        RECT 80.195 196.410 80.515 197.050 ;
        RECT 85.360 196.410 85.680 197.050 ;
        RECT 78.035 192.620 78.785 192.940 ;
        RECT 79.325 192.620 80.075 192.940 ;
        RECT 80.615 192.620 81.365 192.940 ;
        RECT 81.905 192.620 82.655 192.940 ;
        RECT 83.195 192.620 83.945 192.940 ;
        RECT 88.240 192.850 88.880 192.940 ;
        RECT 88.185 192.620 88.935 192.850 ;
        RECT 66.585 191.570 67.335 191.800 ;
        RECT 67.490 191.570 69.010 191.800 ;
        RECT 66.640 191.480 67.280 191.570 ;
        RECT 71.585 191.480 72.335 191.800 ;
        RECT 72.490 190.935 72.720 192.460 ;
        RECT 72.875 191.480 73.625 191.800 ;
        RECT 74.165 191.480 74.915 191.800 ;
        RECT 75.070 190.935 75.300 192.460 ;
        RECT 77.650 191.960 77.895 192.460 ;
        RECT 75.455 191.480 76.205 191.800 ;
        RECT 76.745 191.480 77.495 191.800 ;
        RECT 63.575 190.285 63.895 190.925 ;
        RECT 66.155 190.295 66.475 190.935 ;
        RECT 72.445 190.295 72.765 190.935 ;
        RECT 75.025 190.295 75.345 190.935 ;
        RECT 72.490 190.285 72.720 190.295 ;
        RECT 75.070 190.285 75.300 190.295 ;
        RECT 61.775 187.960 63.295 188.190 ;
        RECT 61.775 187.050 62.005 187.960 ;
        RECT 63.065 187.050 63.295 187.960 ;
        RECT 67.440 187.635 67.760 188.275 ;
        RECT 61.775 186.820 63.295 187.050 ;
        RECT 61.775 186.510 62.005 186.820 ;
        RECT 63.065 186.510 63.295 186.820 ;
        RECT 61.775 186.280 63.295 186.510 ;
        RECT 63.450 186.280 64.200 186.745 ;
        RECT 64.740 186.280 65.885 186.745 ;
        RECT 61.775 185.370 62.005 186.280 ;
        RECT 63.065 185.370 63.295 186.280 ;
        RECT 65.645 185.370 65.885 186.280 ;
        RECT 61.775 185.140 63.295 185.370 ;
        RECT 61.775 184.830 62.005 185.140 ;
        RECT 63.065 184.830 63.295 185.140 ;
        RECT 63.450 185.005 64.200 185.370 ;
        RECT 64.740 185.005 65.885 185.370 ;
        RECT 61.775 184.600 63.295 184.830 ;
        RECT 61.775 183.690 62.005 184.600 ;
        RECT 63.065 183.690 63.295 184.600 ;
        RECT 61.775 183.460 63.295 183.690 ;
        RECT 63.065 181.050 63.295 183.460 ;
        RECT 62.900 180.270 63.655 181.050 ;
        RECT 62.900 179.810 63.650 180.130 ;
        RECT 62.900 178.820 63.145 179.810 ;
        RECT 63.395 178.820 63.650 179.810 ;
        RECT 62.900 178.500 63.650 178.820 ;
        RECT 63.800 180.100 64.120 182.070 ;
        RECT 65.095 180.100 65.325 182.020 ;
        RECT 63.800 179.780 65.325 180.100 ;
        RECT 63.800 178.850 64.120 179.780 ;
        RECT 65.095 178.850 65.325 179.780 ;
        RECT 63.800 178.530 65.325 178.850 ;
        RECT 62.900 177.580 63.650 178.360 ;
        RECT 63.140 175.350 63.460 177.580 ;
        RECT 63.800 176.020 64.120 178.530 ;
        RECT 65.095 176.340 65.325 178.530 ;
        RECT 65.645 176.515 65.885 185.005 ;
        RECT 67.495 182.740 67.725 187.635 ;
        RECT 67.945 186.725 68.585 186.745 ;
        RECT 67.880 186.495 68.630 186.725 ;
        RECT 77.655 186.695 77.895 191.960 ;
        RECT 78.035 191.480 78.785 191.800 ;
        RECT 79.325 191.480 80.075 191.800 ;
        RECT 80.230 190.935 80.460 192.460 ;
        RECT 80.615 191.480 81.365 191.800 ;
        RECT 81.905 191.480 82.655 191.800 ;
        RECT 82.810 190.935 83.040 192.460 ;
        RECT 89.090 192.415 89.330 199.630 ;
        RECT 93.410 198.010 94.050 201.890 ;
        RECT 94.260 200.915 94.490 208.535 ;
        RECT 94.700 207.760 95.340 211.495 ;
        RECT 96.840 209.815 97.070 210.120 ;
        RECT 96.795 208.535 97.115 209.815 ;
        RECT 95.990 207.760 96.630 207.850 ;
        RECT 94.645 207.530 95.395 207.760 ;
        RECT 95.935 207.530 96.685 207.760 ;
        RECT 94.645 201.890 95.395 202.120 ;
        RECT 95.935 201.890 96.685 202.120 ;
        RECT 94.700 201.790 95.340 201.890 ;
        RECT 95.990 201.800 96.630 201.890 ;
        RECT 94.215 199.630 94.535 200.915 ;
        RECT 91.670 197.050 91.900 197.100 ;
        RECT 91.635 196.410 91.955 197.050 ;
        RECT 89.530 192.850 90.170 192.940 ;
        RECT 90.820 192.850 91.460 192.940 ;
        RECT 91.670 192.850 91.900 196.410 ;
        RECT 92.110 192.850 92.750 192.940 ;
        RECT 93.400 192.850 94.040 192.940 ;
        RECT 89.475 192.620 90.225 192.850 ;
        RECT 90.765 192.620 92.805 192.850 ;
        RECT 93.345 192.620 94.095 192.850 ;
        RECT 89.090 191.960 89.320 192.415 ;
        RECT 91.670 191.800 91.900 192.620 ;
        RECT 94.250 192.430 94.490 199.630 ;
        RECT 94.700 198.650 95.335 201.790 ;
        RECT 96.840 200.910 97.070 208.535 ;
        RECT 97.280 207.760 97.920 207.850 ;
        RECT 97.225 207.530 97.975 207.760 ;
        RECT 97.225 201.890 97.975 202.120 ;
        RECT 97.280 201.800 97.920 201.890 ;
        RECT 96.795 199.630 97.115 200.910 ;
        RECT 94.695 198.010 95.335 198.650 ;
        RECT 94.690 192.850 95.330 192.940 ;
        RECT 94.635 192.620 95.385 192.850 ;
        RECT 94.250 191.960 94.480 192.430 ;
        RECT 83.195 191.480 83.945 191.800 ;
        RECT 88.185 191.570 88.935 191.800 ;
        RECT 89.475 191.570 90.225 191.800 ;
        RECT 90.765 191.570 92.805 191.800 ;
        RECT 93.345 191.570 94.095 191.800 ;
        RECT 94.635 191.570 95.385 191.800 ;
        RECT 88.240 191.480 88.880 191.570 ;
        RECT 89.530 191.480 90.170 191.570 ;
        RECT 90.820 191.480 91.460 191.570 ;
        RECT 92.110 191.480 92.750 191.570 ;
        RECT 93.400 191.480 94.040 191.570 ;
        RECT 94.690 191.480 95.330 191.570 ;
        RECT 80.185 190.295 80.505 190.935 ;
        RECT 82.765 190.295 83.085 190.935 ;
        RECT 80.230 190.285 80.460 190.295 ;
        RECT 82.810 190.285 83.040 190.295 ;
        RECT 98.535 186.865 99.595 200.915 ;
        RECT 67.945 186.425 68.585 186.495 ;
        RECT 72.875 186.410 73.615 186.640 ;
        RECT 70.635 185.670 71.045 186.170 ;
        RECT 71.780 186.040 72.715 186.205 ;
        RECT 67.880 185.005 68.630 185.325 ;
        RECT 67.440 182.100 67.760 182.740 ;
        RECT 68.200 182.100 68.520 182.740 ;
        RECT 66.090 179.960 66.730 180.080 ;
        RECT 66.040 179.730 66.790 179.960 ;
        RECT 66.040 178.680 66.790 178.910 ;
        RECT 66.105 178.560 66.745 178.680 ;
        RECT 68.235 176.515 68.465 182.100 ;
        RECT 70.815 180.030 71.045 185.670 ;
        RECT 68.675 179.960 69.315 180.030 ;
        RECT 69.960 179.960 71.045 180.030 ;
        RECT 68.620 179.730 69.370 179.960 ;
        RECT 69.910 179.730 71.045 179.960 ;
        RECT 68.675 179.710 69.315 179.730 ;
        RECT 69.960 179.710 71.045 179.730 ;
        RECT 70.815 178.950 71.045 179.710 ;
        RECT 68.670 178.910 69.310 178.950 ;
        RECT 69.965 178.910 71.045 178.950 ;
        RECT 68.620 178.680 69.370 178.910 ;
        RECT 69.910 178.680 71.045 178.910 ;
        RECT 68.670 178.630 69.310 178.680 ;
        RECT 69.965 178.630 71.045 178.680 ;
        RECT 70.815 176.515 71.045 178.630 ;
        RECT 71.775 185.615 72.715 186.040 ;
        RECT 71.775 183.845 72.415 185.615 ;
        RECT 73.125 185.410 73.355 186.410 ;
        RECT 77.610 186.055 77.930 186.695 ;
        RECT 90.400 186.450 91.040 186.695 ;
        RECT 89.170 186.200 91.275 186.450 ;
        RECT 90.400 186.055 91.040 186.200 ;
        RECT 95.545 185.640 99.595 186.865 ;
        RECT 72.875 184.630 73.615 185.410 ;
        RECT 71.775 176.345 71.990 183.845 ;
        RECT 72.180 176.345 72.415 183.845 ;
        RECT 72.875 183.710 73.615 184.490 ;
        RECT 73.125 182.780 73.355 183.710 ;
        RECT 72.610 182.140 72.930 182.780 ;
        RECT 73.075 182.140 73.395 182.780 ;
        RECT 88.300 182.260 90.405 182.510 ;
        RECT 72.665 179.070 72.895 182.140 ;
        RECT 73.110 179.710 73.750 180.030 ;
        RECT 65.050 176.020 65.370 176.340 ;
        RECT 71.775 176.025 72.415 176.345 ;
        RECT 72.635 176.345 72.895 179.070 ;
        RECT 73.105 178.630 73.745 178.950 ;
        RECT 89.905 178.655 90.225 182.260 ;
        RECT 88.795 178.345 90.890 178.655 ;
        RECT 72.635 176.025 72.955 176.345 ;
        RECT 65.105 175.350 65.425 175.410 ;
        RECT 71.270 175.350 71.590 175.390 ;
        RECT 61.360 175.100 63.465 175.350 ;
        RECT 65.105 175.100 67.210 175.350 ;
        RECT 69.485 175.100 71.590 175.350 ;
        RECT 65.105 175.090 65.425 175.100 ;
        RECT 71.270 175.070 71.590 175.100 ;
        RECT 73.230 175.350 73.550 175.385 ;
        RECT 73.230 175.100 75.335 175.350 ;
        RECT 73.230 175.065 73.550 175.100 ;
        RECT 102.730 167.300 103.370 167.390 ;
        RECT 104.020 167.300 104.660 167.390 ;
        RECT 105.310 167.300 105.950 167.390 ;
        RECT 106.600 167.300 107.240 167.390 ;
        RECT 107.890 167.300 108.530 167.390 ;
        RECT 109.175 167.300 109.815 167.390 ;
        RECT 110.465 167.300 111.105 167.390 ;
        RECT 111.755 167.300 112.395 167.390 ;
        RECT 113.050 167.300 113.690 167.390 ;
        RECT 114.340 167.300 114.980 167.390 ;
        RECT 115.625 167.300 116.265 167.390 ;
        RECT 116.920 167.300 117.560 167.390 ;
        RECT 121.930 167.300 122.570 167.390 ;
        RECT 123.220 167.300 123.860 167.390 ;
        RECT 124.510 167.300 125.150 167.390 ;
        RECT 125.800 167.300 126.440 167.390 ;
        RECT 127.090 167.300 127.730 167.390 ;
        RECT 128.380 167.300 129.020 167.390 ;
        RECT 129.670 167.300 130.310 167.390 ;
        RECT 130.960 167.300 131.600 167.390 ;
        RECT 132.250 167.300 132.890 167.390 ;
        RECT 133.540 167.300 134.180 167.390 ;
        RECT 134.830 167.300 135.470 167.390 ;
        RECT 136.120 167.300 136.760 167.390 ;
        RECT 137.410 167.300 138.050 167.390 ;
        RECT 102.675 167.070 103.425 167.300 ;
        RECT 103.965 167.070 104.715 167.300 ;
        RECT 105.255 167.070 106.005 167.300 ;
        RECT 106.545 167.070 107.295 167.300 ;
        RECT 107.835 167.070 108.585 167.300 ;
        RECT 109.125 167.070 109.875 167.300 ;
        RECT 110.415 167.070 111.165 167.300 ;
        RECT 111.705 167.070 112.455 167.300 ;
        RECT 112.995 167.070 113.745 167.300 ;
        RECT 114.285 167.070 115.035 167.300 ;
        RECT 115.575 167.070 116.325 167.300 ;
        RECT 116.865 167.070 117.615 167.300 ;
        RECT 121.875 167.070 122.625 167.300 ;
        RECT 123.165 167.070 123.915 167.300 ;
        RECT 124.455 167.070 125.205 167.300 ;
        RECT 125.745 167.070 126.495 167.300 ;
        RECT 127.035 167.070 127.785 167.300 ;
        RECT 128.325 167.070 129.075 167.300 ;
        RECT 129.615 167.070 130.365 167.300 ;
        RECT 130.905 167.070 131.655 167.300 ;
        RECT 132.195 167.070 132.945 167.300 ;
        RECT 133.485 167.070 134.235 167.300 ;
        RECT 134.775 167.070 135.525 167.300 ;
        RECT 136.065 167.070 136.815 167.300 ;
        RECT 137.355 167.070 138.105 167.300 ;
        RECT 101.890 108.145 102.530 108.225 ;
        RECT 103.180 108.145 103.820 108.225 ;
        RECT 104.470 108.145 105.110 108.225 ;
        RECT 105.760 108.145 106.400 108.225 ;
        RECT 107.050 108.145 107.690 108.225 ;
        RECT 108.340 108.145 108.980 108.225 ;
        RECT 109.630 108.145 110.270 108.225 ;
        RECT 110.920 108.145 111.560 108.225 ;
        RECT 112.210 108.145 112.850 108.225 ;
        RECT 113.500 108.145 114.140 108.225 ;
        RECT 114.790 108.145 115.430 108.225 ;
        RECT 116.080 108.145 116.720 108.225 ;
        RECT 121.090 108.145 121.730 108.225 ;
        RECT 122.380 108.145 123.020 108.225 ;
        RECT 123.670 108.145 124.310 108.225 ;
        RECT 124.960 108.145 125.600 108.225 ;
        RECT 126.250 108.145 126.890 108.225 ;
        RECT 127.540 108.145 128.180 108.225 ;
        RECT 128.830 108.145 129.470 108.225 ;
        RECT 130.120 108.145 130.760 108.225 ;
        RECT 131.410 108.145 132.050 108.225 ;
        RECT 132.700 108.145 133.340 108.225 ;
        RECT 133.990 108.145 134.630 108.225 ;
        RECT 135.280 108.145 135.920 108.225 ;
        RECT 136.570 108.145 137.210 108.225 ;
        RECT 101.835 107.915 102.585 108.145 ;
        RECT 103.125 107.915 103.875 108.145 ;
        RECT 104.415 107.915 105.165 108.145 ;
        RECT 105.705 107.915 106.455 108.145 ;
        RECT 106.995 107.915 107.745 108.145 ;
        RECT 108.285 107.915 109.035 108.145 ;
        RECT 109.575 107.915 110.325 108.145 ;
        RECT 110.865 107.915 111.615 108.145 ;
        RECT 112.155 107.915 112.905 108.145 ;
        RECT 113.445 107.915 114.195 108.145 ;
        RECT 114.735 107.915 115.485 108.145 ;
        RECT 116.025 107.915 116.775 108.145 ;
        RECT 121.035 107.915 121.785 108.145 ;
        RECT 122.325 107.915 123.075 108.145 ;
        RECT 123.615 107.915 124.365 108.145 ;
        RECT 124.905 107.915 125.655 108.145 ;
        RECT 126.195 107.915 126.945 108.145 ;
        RECT 127.485 107.915 128.235 108.145 ;
        RECT 128.775 107.915 129.525 108.145 ;
        RECT 130.065 107.915 130.815 108.145 ;
        RECT 131.355 107.915 132.105 108.145 ;
        RECT 132.645 107.915 133.395 108.145 ;
        RECT 133.935 107.915 134.685 108.145 ;
        RECT 135.225 107.915 135.975 108.145 ;
        RECT 136.515 107.915 137.265 108.145 ;
        RECT 101.890 107.905 102.530 107.915 ;
        RECT 103.180 107.905 103.820 107.915 ;
        RECT 104.470 107.905 105.110 107.915 ;
        RECT 105.760 107.905 106.400 107.915 ;
        RECT 107.050 107.905 107.690 107.915 ;
        RECT 108.340 107.905 108.980 107.915 ;
        RECT 109.630 107.905 110.270 107.915 ;
        RECT 110.920 107.905 111.560 107.915 ;
        RECT 112.210 107.905 112.850 107.915 ;
        RECT 113.500 107.905 114.140 107.915 ;
        RECT 114.790 107.905 115.430 107.915 ;
        RECT 116.080 107.905 116.720 107.915 ;
        RECT 121.090 107.905 121.730 107.915 ;
        RECT 122.380 107.905 123.020 107.915 ;
        RECT 123.670 107.905 124.310 107.915 ;
        RECT 124.960 107.905 125.600 107.915 ;
        RECT 126.250 107.905 126.890 107.915 ;
        RECT 127.540 107.905 128.180 107.915 ;
        RECT 128.830 107.905 129.470 107.915 ;
        RECT 130.120 107.905 130.760 107.915 ;
        RECT 131.410 107.905 132.050 107.915 ;
        RECT 132.700 107.905 133.340 107.915 ;
        RECT 133.990 107.905 134.630 107.915 ;
        RECT 135.280 107.905 135.920 107.915 ;
        RECT 136.570 107.905 137.210 107.915 ;
        RECT 74.195 106.815 74.515 107.455 ;
        RECT 79.355 106.815 79.675 107.455 ;
        RECT 84.515 106.815 84.835 107.455 ;
        RECT 71.615 105.060 71.935 105.700 ;
        RECT 64.025 103.350 64.345 103.990 ;
        RECT 70.815 103.985 71.135 103.990 ;
        RECT 70.815 103.350 71.455 103.985 ;
        RECT 60.200 102.060 61.905 102.065 ;
        RECT 60.200 101.740 62.630 102.060 ;
        RECT 63.170 101.965 63.920 102.060 ;
        RECT 63.165 101.740 63.920 101.965 ;
        RECT 60.200 96.330 60.430 101.740 ;
        RECT 60.585 101.735 61.335 101.740 ;
        RECT 61.875 101.735 62.625 101.740 ;
        RECT 63.165 101.735 63.915 101.740 ;
        RECT 61.490 97.220 61.720 101.530 ;
        RECT 61.490 96.530 61.725 97.220 ;
        RECT 61.495 96.330 61.725 96.530 ;
        RECT 60.200 96.010 62.630 96.330 ;
        RECT 63.170 96.325 63.920 96.330 ;
        RECT 63.165 96.095 63.920 96.325 ;
        RECT 63.170 96.010 63.920 96.095 ;
        RECT 60.200 96.005 61.725 96.010 ;
        RECT 63.220 96.005 63.860 96.010 ;
        RECT 61.495 87.055 61.725 96.005 ;
        RECT 64.070 94.725 64.300 103.350 ;
        RECT 71.135 103.345 71.455 103.350 ;
        RECT 66.475 102.060 68.170 102.065 ;
        RECT 64.460 101.965 65.210 102.060 ;
        RECT 65.750 101.965 68.170 102.060 ;
        RECT 64.455 101.740 65.210 101.965 ;
        RECT 65.745 101.740 68.170 101.965 ;
        RECT 64.455 101.735 65.205 101.740 ;
        RECT 65.745 101.735 66.495 101.740 ;
        RECT 67.035 101.735 67.785 101.740 ;
        RECT 66.650 97.210 66.880 101.530 ;
        RECT 66.650 96.530 66.885 97.210 ;
        RECT 66.655 96.335 66.885 96.530 ;
        RECT 67.940 96.335 68.170 101.740 ;
        RECT 70.755 101.735 71.505 102.055 ;
        RECT 66.475 96.330 68.170 96.335 ;
        RECT 64.460 96.325 65.210 96.330 ;
        RECT 65.750 96.325 68.170 96.330 ;
        RECT 64.455 96.095 65.210 96.325 ;
        RECT 65.745 96.095 68.170 96.325 ;
        RECT 64.460 96.010 65.210 96.095 ;
        RECT 65.750 96.010 68.170 96.095 ;
        RECT 64.510 96.005 65.150 96.010 ;
        RECT 65.800 96.005 66.440 96.010 ;
        RECT 64.025 94.085 64.345 94.725 ;
        RECT 61.930 87.055 62.570 87.145 ;
        RECT 60.200 86.825 61.725 87.055 ;
        RECT 61.875 86.825 62.625 87.055 ;
        RECT 60.200 86.005 60.430 86.825 ;
        RECT 61.490 86.005 61.725 86.825 ;
        RECT 60.200 85.775 61.725 86.005 ;
        RECT 61.875 85.775 62.625 86.005 ;
        RECT 61.930 85.685 62.570 85.775 ;
        RECT 62.780 85.130 63.010 86.665 ;
        RECT 64.070 86.165 64.300 94.085 ;
        RECT 65.800 87.055 66.440 87.145 ;
        RECT 66.655 87.055 66.885 96.010 ;
        RECT 70.755 96.005 71.505 96.325 ;
        RECT 71.660 92.855 71.890 105.060 ;
        RECT 72.045 101.735 72.795 102.055 ;
        RECT 73.335 101.735 74.085 102.055 ;
        RECT 72.045 96.005 72.795 96.325 ;
        RECT 73.335 96.005 74.085 96.325 ;
        RECT 71.615 92.215 71.935 92.855 ;
        RECT 74.240 91.255 74.470 106.815 ;
        RECT 76.775 105.060 77.095 105.700 ;
        RECT 74.625 101.735 75.375 102.055 ;
        RECT 75.915 101.735 76.665 102.055 ;
        RECT 76.825 101.530 77.055 105.060 ;
        RECT 77.205 101.735 77.955 102.055 ;
        RECT 78.495 101.735 79.245 102.055 ;
        RECT 76.820 96.530 77.055 101.530 ;
        RECT 74.625 96.005 75.375 96.325 ;
        RECT 75.915 96.005 76.665 96.325 ;
        RECT 76.825 92.855 77.055 96.530 ;
        RECT 77.205 96.005 77.955 96.325 ;
        RECT 78.495 96.005 79.245 96.325 ;
        RECT 76.775 92.215 77.095 92.855 ;
        RECT 74.195 90.615 74.515 91.255 ;
        RECT 65.745 86.825 66.495 87.055 ;
        RECT 66.655 86.825 68.170 87.055 ;
        RECT 70.745 86.825 71.495 87.145 ;
        RECT 72.035 86.825 72.785 87.145 ;
        RECT 73.325 86.825 74.075 87.145 ;
        RECT 74.615 86.825 75.365 87.145 ;
        RECT 75.905 86.825 76.655 87.145 ;
        RECT 66.655 86.665 66.885 86.825 ;
        RECT 65.360 85.140 65.590 86.665 ;
        RECT 66.650 86.650 66.885 86.665 ;
        RECT 66.650 86.005 66.880 86.650 ;
        RECT 67.940 86.005 68.170 86.825 ;
        RECT 76.825 86.665 77.055 92.215 ;
        RECT 79.400 91.255 79.630 106.815 ;
        RECT 81.935 105.060 82.255 105.700 ;
        RECT 79.785 101.735 80.535 102.055 ;
        RECT 81.075 101.735 81.825 102.055 ;
        RECT 79.785 96.005 80.535 96.325 ;
        RECT 81.075 96.005 81.825 96.325 ;
        RECT 81.980 92.855 82.210 105.060 ;
        RECT 82.365 101.735 83.115 102.055 ;
        RECT 83.655 101.735 84.405 102.055 ;
        RECT 82.365 96.005 83.115 96.325 ;
        RECT 83.655 96.005 84.405 96.325 ;
        RECT 81.935 92.215 82.255 92.855 ;
        RECT 84.560 91.255 84.790 106.815 ;
        RECT 90.795 102.740 91.115 104.075 ;
        RECT 84.945 101.735 85.695 102.055 ;
        RECT 89.990 101.965 90.630 102.055 ;
        RECT 89.935 101.735 90.685 101.965 ;
        RECT 84.945 96.005 85.695 96.325 ;
        RECT 89.935 96.095 90.685 96.325 ;
        RECT 89.990 96.005 90.630 96.095 ;
        RECT 90.840 95.115 91.070 102.740 ;
        RECT 91.280 101.965 91.920 102.055 ;
        RECT 92.570 101.965 93.210 105.700 ;
        RECT 93.420 104.020 93.650 104.300 ;
        RECT 93.375 102.740 93.695 104.020 ;
        RECT 91.225 101.735 91.975 101.965 ;
        RECT 92.515 101.735 93.265 101.965 ;
        RECT 91.225 96.095 91.975 96.325 ;
        RECT 92.515 96.095 93.265 96.325 ;
        RECT 91.280 96.005 91.920 96.095 ;
        RECT 88.215 93.835 88.535 95.115 ;
        RECT 90.795 93.835 91.115 95.115 ;
        RECT 79.355 90.615 79.675 91.255 ;
        RECT 84.520 90.615 84.840 91.255 ;
        RECT 77.195 86.825 77.945 87.145 ;
        RECT 78.485 86.825 79.235 87.145 ;
        RECT 79.775 86.825 80.525 87.145 ;
        RECT 81.065 86.825 81.815 87.145 ;
        RECT 82.355 86.825 83.105 87.145 ;
        RECT 87.400 87.055 88.040 87.145 ;
        RECT 87.345 86.825 88.095 87.055 ;
        RECT 65.745 85.775 66.495 86.005 ;
        RECT 66.650 85.775 68.170 86.005 ;
        RECT 65.800 85.685 66.440 85.775 ;
        RECT 70.745 85.685 71.495 86.005 ;
        RECT 71.650 85.140 71.880 86.665 ;
        RECT 72.035 85.685 72.785 86.005 ;
        RECT 73.325 85.685 74.075 86.005 ;
        RECT 74.230 85.140 74.460 86.665 ;
        RECT 76.810 86.165 77.055 86.665 ;
        RECT 74.615 85.685 75.365 86.005 ;
        RECT 75.905 85.685 76.655 86.005 ;
        RECT 62.735 84.490 63.055 85.130 ;
        RECT 65.315 84.500 65.635 85.140 ;
        RECT 71.605 84.500 71.925 85.140 ;
        RECT 74.185 84.500 74.505 85.140 ;
        RECT 71.650 84.490 71.880 84.500 ;
        RECT 74.230 84.490 74.460 84.500 ;
        RECT 60.935 82.165 62.455 82.395 ;
        RECT 60.935 81.255 61.165 82.165 ;
        RECT 62.225 81.255 62.455 82.165 ;
        RECT 66.600 81.840 66.920 82.480 ;
        RECT 60.935 81.025 62.455 81.255 ;
        RECT 60.935 80.715 61.165 81.025 ;
        RECT 62.225 80.715 62.455 81.025 ;
        RECT 60.935 80.485 62.455 80.715 ;
        RECT 62.610 80.485 63.360 80.950 ;
        RECT 63.900 80.485 65.045 80.950 ;
        RECT 60.935 79.575 61.165 80.485 ;
        RECT 62.225 79.575 62.455 80.485 ;
        RECT 64.805 79.575 65.045 80.485 ;
        RECT 60.935 79.345 62.455 79.575 ;
        RECT 60.935 79.035 61.165 79.345 ;
        RECT 62.225 79.035 62.455 79.345 ;
        RECT 62.610 79.210 63.360 79.575 ;
        RECT 63.900 79.210 65.045 79.575 ;
        RECT 60.935 78.805 62.455 79.035 ;
        RECT 60.935 77.895 61.165 78.805 ;
        RECT 62.225 77.895 62.455 78.805 ;
        RECT 60.935 77.665 62.455 77.895 ;
        RECT 62.225 75.255 62.455 77.665 ;
        RECT 62.060 74.475 62.815 75.255 ;
        RECT 62.060 74.015 62.810 74.335 ;
        RECT 62.060 73.025 62.305 74.015 ;
        RECT 62.555 73.025 62.810 74.015 ;
        RECT 62.060 72.705 62.810 73.025 ;
        RECT 62.960 74.305 63.280 76.275 ;
        RECT 64.255 74.305 64.485 76.225 ;
        RECT 62.960 73.985 64.485 74.305 ;
        RECT 62.960 73.055 63.280 73.985 ;
        RECT 64.255 73.055 64.485 73.985 ;
        RECT 62.960 72.735 64.485 73.055 ;
        RECT 62.060 71.785 62.810 72.565 ;
        RECT 62.300 69.555 62.620 71.785 ;
        RECT 62.960 70.225 63.280 72.735 ;
        RECT 64.255 70.545 64.485 72.735 ;
        RECT 64.805 70.720 65.045 79.210 ;
        RECT 66.655 76.945 66.885 81.840 ;
        RECT 67.105 80.930 67.745 80.950 ;
        RECT 67.040 80.700 67.790 80.930 ;
        RECT 76.815 80.900 77.055 86.165 ;
        RECT 77.195 85.685 77.945 86.005 ;
        RECT 78.485 85.685 79.235 86.005 ;
        RECT 79.390 85.140 79.620 86.665 ;
        RECT 79.775 85.685 80.525 86.005 ;
        RECT 81.065 85.685 81.815 86.005 ;
        RECT 81.970 85.140 82.200 86.665 ;
        RECT 88.250 86.620 88.490 93.835 ;
        RECT 92.570 92.215 93.210 96.095 ;
        RECT 93.420 95.120 93.650 102.740 ;
        RECT 93.860 101.965 94.500 105.700 ;
        RECT 96.000 104.020 96.230 104.325 ;
        RECT 95.955 102.740 96.275 104.020 ;
        RECT 95.150 101.965 95.790 102.055 ;
        RECT 93.805 101.735 94.555 101.965 ;
        RECT 95.095 101.735 95.845 101.965 ;
        RECT 93.805 96.095 94.555 96.325 ;
        RECT 95.095 96.095 95.845 96.325 ;
        RECT 93.860 95.995 94.500 96.095 ;
        RECT 95.150 96.005 95.790 96.095 ;
        RECT 93.375 93.835 93.695 95.120 ;
        RECT 90.830 91.255 91.060 91.305 ;
        RECT 90.795 90.615 91.115 91.255 ;
        RECT 88.690 87.055 89.330 87.145 ;
        RECT 89.980 87.055 90.620 87.145 ;
        RECT 90.830 87.055 91.060 90.615 ;
        RECT 91.270 87.055 91.910 87.145 ;
        RECT 92.560 87.055 93.200 87.145 ;
        RECT 88.635 86.825 89.385 87.055 ;
        RECT 89.925 86.825 91.965 87.055 ;
        RECT 92.505 86.825 93.255 87.055 ;
        RECT 88.250 86.165 88.480 86.620 ;
        RECT 90.830 86.005 91.060 86.825 ;
        RECT 93.410 86.635 93.650 93.835 ;
        RECT 93.860 92.855 94.495 95.995 ;
        RECT 96.000 95.115 96.230 102.740 ;
        RECT 96.440 101.965 97.080 102.055 ;
        RECT 96.385 101.735 97.135 101.965 ;
        RECT 96.385 96.095 97.135 96.325 ;
        RECT 96.440 96.005 97.080 96.095 ;
        RECT 95.955 93.835 96.275 95.115 ;
        RECT 93.855 92.215 94.495 92.855 ;
        RECT 93.850 87.055 94.490 87.145 ;
        RECT 93.795 86.825 94.545 87.055 ;
        RECT 93.410 86.165 93.640 86.635 ;
        RECT 82.355 85.685 83.105 86.005 ;
        RECT 87.345 85.775 88.095 86.005 ;
        RECT 88.635 85.775 89.385 86.005 ;
        RECT 89.925 85.775 91.965 86.005 ;
        RECT 92.505 85.775 93.255 86.005 ;
        RECT 93.795 85.775 94.545 86.005 ;
        RECT 87.400 85.685 88.040 85.775 ;
        RECT 88.690 85.685 89.330 85.775 ;
        RECT 89.980 85.685 90.620 85.775 ;
        RECT 91.270 85.685 91.910 85.775 ;
        RECT 92.560 85.685 93.200 85.775 ;
        RECT 93.850 85.685 94.490 85.775 ;
        RECT 79.345 84.500 79.665 85.140 ;
        RECT 81.925 84.500 82.245 85.140 ;
        RECT 79.390 84.490 79.620 84.500 ;
        RECT 81.970 84.490 82.200 84.500 ;
        RECT 97.695 81.070 98.755 95.120 ;
        RECT 67.105 80.630 67.745 80.700 ;
        RECT 72.035 80.615 72.775 80.845 ;
        RECT 69.795 79.875 70.205 80.375 ;
        RECT 70.940 80.245 71.875 80.410 ;
        RECT 67.040 79.210 67.790 79.530 ;
        RECT 66.600 76.305 66.920 76.945 ;
        RECT 67.360 76.305 67.680 76.945 ;
        RECT 65.250 74.165 65.890 74.285 ;
        RECT 65.200 73.935 65.950 74.165 ;
        RECT 65.200 72.885 65.950 73.115 ;
        RECT 65.265 72.765 65.905 72.885 ;
        RECT 67.395 70.720 67.625 76.305 ;
        RECT 69.975 74.235 70.205 79.875 ;
        RECT 67.835 74.165 68.475 74.235 ;
        RECT 69.120 74.165 70.205 74.235 ;
        RECT 67.780 73.935 68.530 74.165 ;
        RECT 69.070 73.935 70.205 74.165 ;
        RECT 67.835 73.915 68.475 73.935 ;
        RECT 69.120 73.915 70.205 73.935 ;
        RECT 69.975 73.155 70.205 73.915 ;
        RECT 67.830 73.115 68.470 73.155 ;
        RECT 69.125 73.115 70.205 73.155 ;
        RECT 67.780 72.885 68.530 73.115 ;
        RECT 69.070 72.885 70.205 73.115 ;
        RECT 67.830 72.835 68.470 72.885 ;
        RECT 69.125 72.835 70.205 72.885 ;
        RECT 69.975 70.720 70.205 72.835 ;
        RECT 70.935 79.820 71.875 80.245 ;
        RECT 70.935 78.050 71.575 79.820 ;
        RECT 72.285 79.615 72.515 80.615 ;
        RECT 76.770 80.260 77.090 80.900 ;
        RECT 89.560 80.655 90.200 80.900 ;
        RECT 88.330 80.405 90.435 80.655 ;
        RECT 89.560 80.260 90.200 80.405 ;
        RECT 94.705 79.845 98.755 81.070 ;
        RECT 72.035 78.835 72.775 79.615 ;
        RECT 70.935 70.550 71.150 78.050 ;
        RECT 71.340 70.550 71.575 78.050 ;
        RECT 72.035 77.915 72.775 78.695 ;
        RECT 72.285 76.985 72.515 77.915 ;
        RECT 71.770 76.345 72.090 76.985 ;
        RECT 72.235 76.345 72.555 76.985 ;
        RECT 87.460 76.465 89.565 76.715 ;
        RECT 71.825 73.275 72.055 76.345 ;
        RECT 72.270 73.915 72.910 74.235 ;
        RECT 64.210 70.225 64.530 70.545 ;
        RECT 70.935 70.230 71.575 70.550 ;
        RECT 71.795 70.550 72.055 73.275 ;
        RECT 72.265 72.835 72.905 73.155 ;
        RECT 89.065 72.860 89.385 76.465 ;
        RECT 87.955 72.550 90.050 72.860 ;
        RECT 71.795 70.230 72.115 70.550 ;
        RECT 64.265 69.555 64.585 69.615 ;
        RECT 70.430 69.555 70.750 69.595 ;
        RECT 60.520 69.305 62.625 69.555 ;
        RECT 64.265 69.305 66.370 69.555 ;
        RECT 68.645 69.305 70.750 69.555 ;
        RECT 64.265 69.295 64.585 69.305 ;
        RECT 70.430 69.275 70.750 69.305 ;
        RECT 72.390 69.555 72.710 69.590 ;
        RECT 72.390 69.305 74.495 69.555 ;
        RECT 72.390 69.270 72.710 69.305 ;
        RECT 101.890 61.505 102.530 61.595 ;
        RECT 103.180 61.505 103.820 61.595 ;
        RECT 104.470 61.505 105.110 61.595 ;
        RECT 105.760 61.505 106.400 61.595 ;
        RECT 107.050 61.505 107.690 61.595 ;
        RECT 108.335 61.505 108.975 61.595 ;
        RECT 109.625 61.505 110.265 61.595 ;
        RECT 110.915 61.505 111.555 61.595 ;
        RECT 112.210 61.505 112.850 61.595 ;
        RECT 113.500 61.505 114.140 61.595 ;
        RECT 114.785 61.505 115.425 61.595 ;
        RECT 116.080 61.505 116.720 61.595 ;
        RECT 121.090 61.505 121.730 61.595 ;
        RECT 122.380 61.505 123.020 61.595 ;
        RECT 123.670 61.505 124.310 61.595 ;
        RECT 124.960 61.505 125.600 61.595 ;
        RECT 126.250 61.505 126.890 61.595 ;
        RECT 127.540 61.505 128.180 61.595 ;
        RECT 128.830 61.505 129.470 61.595 ;
        RECT 130.120 61.505 130.760 61.595 ;
        RECT 131.410 61.505 132.050 61.595 ;
        RECT 132.700 61.505 133.340 61.595 ;
        RECT 133.990 61.505 134.630 61.595 ;
        RECT 135.280 61.505 135.920 61.595 ;
        RECT 136.570 61.505 137.210 61.595 ;
        RECT 101.835 61.275 102.585 61.505 ;
        RECT 103.125 61.275 103.875 61.505 ;
        RECT 104.415 61.275 105.165 61.505 ;
        RECT 105.705 61.275 106.455 61.505 ;
        RECT 106.995 61.275 107.745 61.505 ;
        RECT 108.285 61.275 109.035 61.505 ;
        RECT 109.575 61.275 110.325 61.505 ;
        RECT 110.865 61.275 111.615 61.505 ;
        RECT 112.155 61.275 112.905 61.505 ;
        RECT 113.445 61.275 114.195 61.505 ;
        RECT 114.735 61.275 115.485 61.505 ;
        RECT 116.025 61.275 116.775 61.505 ;
        RECT 121.035 61.275 121.785 61.505 ;
        RECT 122.325 61.275 123.075 61.505 ;
        RECT 123.615 61.275 124.365 61.505 ;
        RECT 124.905 61.275 125.655 61.505 ;
        RECT 126.195 61.275 126.945 61.505 ;
        RECT 127.485 61.275 128.235 61.505 ;
        RECT 128.775 61.275 129.525 61.505 ;
        RECT 130.065 61.275 130.815 61.505 ;
        RECT 131.355 61.275 132.105 61.505 ;
        RECT 132.645 61.275 133.395 61.505 ;
        RECT 133.935 61.275 134.685 61.505 ;
        RECT 135.225 61.275 135.975 61.505 ;
        RECT 136.515 61.275 137.265 61.505 ;
      LAYER met2 ;
        RECT 102.455 213.540 138.230 214.020 ;
        RECT 75.035 212.610 85.675 213.250 ;
        RECT 8.755 210.405 42.695 211.730 ;
        RECT 72.455 210.855 95.340 211.495 ;
        RECT 64.865 209.145 86.475 209.785 ;
        RECT 64.910 209.140 86.475 209.145 ;
        RECT 62.720 207.535 67.280 207.855 ;
        RECT 71.650 207.850 72.340 209.140 ;
        RECT 78.725 207.850 79.415 209.140 ;
        RECT 85.785 207.850 86.475 209.140 ;
        RECT 91.635 208.535 134.600 209.870 ;
        RECT 90.830 207.850 97.910 207.860 ;
        RECT 62.770 207.530 63.410 207.535 ;
        RECT 64.060 207.530 64.700 207.535 ;
        RECT 65.350 207.530 65.990 207.535 ;
        RECT 66.635 207.530 67.275 207.535 ;
        RECT 71.650 207.530 86.480 207.850 ;
        RECT 90.830 207.530 97.920 207.850 ;
        RECT 62.770 201.805 67.280 202.125 ;
        RECT 64.060 201.800 64.700 201.805 ;
        RECT 65.350 201.800 65.990 201.805 ;
        RECT 66.640 201.800 67.280 201.805 ;
        RECT 71.650 201.800 86.480 202.120 ;
        RECT 71.650 200.520 72.340 201.800 ;
        RECT 78.755 200.520 79.445 201.800 ;
        RECT 85.790 200.520 86.480 201.800 ;
        RECT 90.815 201.790 97.920 202.120 ;
        RECT 89.060 200.910 134.600 200.915 ;
        RECT 64.865 199.880 86.480 200.520 ;
        RECT 64.910 199.875 86.480 199.880 ;
        RECT 89.055 199.630 134.600 200.910 ;
        RECT 72.455 198.010 95.335 198.650 ;
        RECT 8.755 195.705 12.890 196.665 ;
        RECT 75.035 196.410 91.955 197.050 ;
        RECT 62.770 192.620 63.410 192.940 ;
        RECT 66.640 192.620 67.280 192.940 ;
        RECT 71.640 192.590 83.890 192.960 ;
        RECT 88.240 192.620 95.330 192.940 ;
        RECT 62.770 191.480 63.410 191.800 ;
        RECT 66.640 191.480 67.280 191.800 ;
        RECT 71.640 191.455 83.890 191.825 ;
        RECT 88.240 191.480 95.330 191.800 ;
        RECT 63.575 190.285 83.085 190.935 ;
        RECT 67.440 187.635 83.750 188.275 ;
        RECT 63.490 186.425 68.585 186.745 ;
        RECT 77.610 186.055 91.045 186.695 ;
        RECT 63.450 185.005 68.585 185.325 ;
        RECT 72.875 183.710 73.615 185.410 ;
        RECT 67.440 182.100 68.520 182.740 ;
        RECT 72.610 182.140 73.395 182.780 ;
        RECT 62.885 181.275 90.225 181.915 ;
        RECT 62.900 180.270 63.655 181.050 ;
        RECT 62.900 179.810 63.650 180.270 ;
        RECT 64.245 180.080 66.715 180.100 ;
        RECT 64.245 179.780 66.730 180.080 ;
        RECT 66.090 179.760 66.730 179.780 ;
        RECT 68.675 179.710 73.750 180.030 ;
        RECT 66.105 178.850 66.745 178.880 ;
        RECT 62.900 177.580 63.650 178.820 ;
        RECT 64.245 178.530 66.745 178.850 ;
        RECT 68.670 178.630 73.745 178.950 ;
        RECT 63.800 176.020 65.425 176.340 ;
        RECT 65.105 175.090 65.425 176.020 ;
        RECT 71.270 176.025 72.415 176.345 ;
        RECT 72.635 176.025 73.550 176.345 ;
        RECT 71.270 175.070 71.590 176.025 ;
        RECT 73.230 175.065 73.550 176.025 ;
        RECT 102.460 167.070 138.230 167.480 ;
        RECT 101.615 107.745 137.390 108.225 ;
        RECT 74.195 106.815 84.835 107.455 ;
        RECT 71.615 105.060 94.500 105.700 ;
        RECT 64.025 103.350 85.635 103.990 ;
        RECT 64.070 103.345 85.635 103.350 ;
        RECT 61.880 101.740 66.440 102.060 ;
        RECT 70.810 102.055 71.500 103.345 ;
        RECT 77.885 102.055 78.575 103.345 ;
        RECT 84.945 102.055 85.635 103.345 ;
        RECT 90.795 102.740 133.760 104.075 ;
        RECT 89.990 102.055 97.070 102.065 ;
        RECT 61.930 101.735 62.570 101.740 ;
        RECT 63.220 101.735 63.860 101.740 ;
        RECT 64.510 101.735 65.150 101.740 ;
        RECT 65.795 101.735 66.435 101.740 ;
        RECT 70.810 101.735 85.640 102.055 ;
        RECT 89.990 101.735 97.080 102.055 ;
        RECT 61.930 96.010 66.440 96.330 ;
        RECT 63.220 96.005 63.860 96.010 ;
        RECT 64.510 96.005 65.150 96.010 ;
        RECT 65.800 96.005 66.440 96.010 ;
        RECT 70.810 96.005 85.640 96.325 ;
        RECT 70.810 94.725 71.500 96.005 ;
        RECT 77.915 94.725 78.605 96.005 ;
        RECT 84.950 94.725 85.640 96.005 ;
        RECT 89.975 95.995 97.080 96.325 ;
        RECT 88.220 95.115 133.760 95.120 ;
        RECT 64.025 94.085 85.640 94.725 ;
        RECT 64.070 94.080 85.640 94.085 ;
        RECT 88.215 93.835 133.760 95.115 ;
        RECT 71.615 92.215 94.495 92.855 ;
        RECT 74.195 90.615 91.115 91.255 ;
        RECT 61.930 86.825 62.570 87.145 ;
        RECT 65.800 86.825 66.440 87.145 ;
        RECT 70.800 86.795 83.050 87.165 ;
        RECT 87.400 86.825 94.490 87.145 ;
        RECT 61.930 85.685 62.570 86.005 ;
        RECT 65.800 85.685 66.440 86.005 ;
        RECT 70.800 85.660 83.050 86.030 ;
        RECT 87.400 85.685 94.490 86.005 ;
        RECT 62.735 84.490 82.245 85.140 ;
        RECT 66.600 81.840 82.910 82.480 ;
        RECT 62.650 80.630 67.745 80.950 ;
        RECT 76.770 80.260 90.205 80.900 ;
        RECT 62.610 79.210 67.745 79.530 ;
        RECT 72.035 77.915 72.775 79.615 ;
        RECT 66.600 76.305 67.680 76.945 ;
        RECT 71.770 76.345 72.555 76.985 ;
        RECT 62.045 75.480 89.385 76.120 ;
        RECT 62.060 74.475 62.815 75.255 ;
        RECT 62.060 74.015 62.810 74.475 ;
        RECT 63.405 74.285 65.875 74.305 ;
        RECT 63.405 73.985 65.890 74.285 ;
        RECT 65.250 73.965 65.890 73.985 ;
        RECT 67.835 73.915 72.910 74.235 ;
        RECT 65.265 73.055 65.905 73.085 ;
        RECT 62.060 71.785 62.810 73.025 ;
        RECT 63.405 72.735 65.905 73.055 ;
        RECT 67.830 72.835 72.905 73.155 ;
        RECT 62.960 70.225 64.585 70.545 ;
        RECT 64.265 69.295 64.585 70.225 ;
        RECT 70.430 70.230 71.575 70.550 ;
        RECT 71.795 70.230 72.710 70.550 ;
        RECT 70.430 69.275 70.750 70.230 ;
        RECT 72.390 69.270 72.710 70.230 ;
        RECT 101.620 61.275 137.390 61.685 ;
      LAYER met3 ;
        RECT 78.225 195.230 79.910 209.785 ;
        RECT 62.885 181.275 63.290 192.965 ;
        RECT 66.755 181.275 67.160 192.965 ;
        RECT 71.775 187.635 72.145 192.960 ;
        RECT 78.225 164.315 79.905 195.230 ;
        RECT 83.380 191.825 83.750 192.960 ;
        RECT 83.375 191.455 83.750 191.825 ;
        RECT 83.380 187.635 83.750 191.455 ;
        RECT 102.470 167.070 103.630 214.020 ;
        RECT 105.050 167.070 106.280 214.020 ;
        RECT 130.850 167.070 132.010 214.020 ;
        RECT 133.430 167.070 134.590 214.020 ;
        RECT 59.555 150.590 75.415 162.990 ;
        RECT 76.615 150.590 92.475 162.990 ;
        RECT 93.675 150.590 109.535 162.990 ;
        RECT 59.555 136.990 75.415 149.390 ;
        RECT 76.615 136.990 92.475 149.390 ;
        RECT 93.675 136.990 109.535 149.390 ;
        RECT 59.555 123.390 75.415 135.790 ;
        RECT 76.615 123.390 92.475 135.790 ;
        RECT 93.675 123.390 109.535 135.790 ;
        RECT 77.385 89.435 79.070 103.990 ;
        RECT 62.045 75.480 62.450 87.170 ;
        RECT 65.915 75.480 66.320 87.170 ;
        RECT 70.935 81.840 71.305 87.165 ;
        RECT 77.385 58.520 79.065 89.435 ;
        RECT 82.540 86.030 82.910 87.165 ;
        RECT 82.535 85.660 82.910 86.030 ;
        RECT 82.540 81.840 82.910 85.660 ;
        RECT 101.630 61.275 102.790 108.225 ;
        RECT 104.210 61.275 105.440 108.225 ;
        RECT 130.010 61.275 131.170 108.225 ;
        RECT 132.590 61.275 133.750 108.225 ;
        RECT 58.715 44.795 74.575 57.195 ;
        RECT 75.775 44.795 91.635 57.195 ;
        RECT 92.835 44.795 108.695 57.195 ;
        RECT 58.715 31.195 74.575 43.595 ;
        RECT 75.775 31.195 91.635 43.595 ;
        RECT 92.835 31.195 108.695 43.595 ;
        RECT 58.715 17.595 74.575 29.995 ;
        RECT 75.775 17.595 91.635 29.995 ;
        RECT 92.835 17.595 108.695 29.995 ;
      LAYER met4 ;
        RECT 72.070 224.760 72.370 225.760 ;
        RECT 74.830 224.760 75.130 225.760 ;
        RECT 77.590 224.760 77.890 225.760 ;
        RECT 80.350 224.760 80.650 225.760 ;
        RECT 83.110 224.760 83.410 225.760 ;
        RECT 85.870 224.760 86.170 225.760 ;
        RECT 88.630 224.760 88.930 225.760 ;
        RECT 91.390 224.760 91.690 225.760 ;
        RECT 94.150 224.760 94.450 225.760 ;
        RECT 96.910 224.760 97.210 225.760 ;
        RECT 99.670 224.760 99.970 225.760 ;
        RECT 102.430 224.760 102.730 225.760 ;
        RECT 105.190 224.760 105.490 225.760 ;
        RECT 107.950 224.760 108.250 225.760 ;
        RECT 110.710 224.760 111.010 225.760 ;
        RECT 113.470 224.760 113.770 225.760 ;
        RECT 116.230 224.760 116.530 225.760 ;
        RECT 118.990 224.760 119.290 225.760 ;
        RECT 121.750 224.760 122.050 225.760 ;
        RECT 124.510 224.760 124.810 225.760 ;
        RECT 127.270 224.760 127.570 225.760 ;
        RECT 130.030 224.760 130.330 225.760 ;
        RECT 132.790 224.760 133.090 225.760 ;
        RECT 135.550 224.760 135.850 225.760 ;
        RECT 138.310 224.760 138.610 225.760 ;
        RECT 141.070 224.760 141.370 225.760 ;
        RECT 143.830 224.760 144.130 225.760 ;
        RECT 146.590 224.760 146.890 225.760 ;
        RECT 74.895 164.315 109.960 165.095 ;
        RECT 74.895 122.790 75.840 164.315 ;
        RECT 91.955 122.790 92.900 164.315 ;
        RECT 109.015 122.790 109.960 164.315 ;
        RECT 74.055 58.520 109.120 59.300 ;
        RECT 74.055 16.995 75.000 58.520 ;
        RECT 91.115 16.995 92.060 58.520 ;
        RECT 108.175 16.995 109.120 58.520 ;
        RECT 16.570 0.000 17.470 1.000 ;
        RECT 35.890 0.000 36.790 1.000 ;
        RECT 55.210 0.000 56.110 0.990 ;
  END
END tt_um_LDO23t4
END LIBRARY

